Omron Sysmac Studio project EIP 自定义指令功能 20240814 (Sysmac Studio 1.50.0.64013, StandardProject)
(* 指令扩充 *)

# Controller new_Controller_0: NX102-1100 version 1.47
Task PrimaryTask (priority 4, period or condition 4000): program0

TYPE 机器人状态反馈1 : UNION
    motionstate1 : BYTE;
    state1 : ARRAY[0..7] OF BOOL;
END_UNION END_TYPE
TYPE 机器人状态反馈2 : UNION
    motionstate2 : BYTE;
    state2 : ARRAY[0..7] OF BOOL;
END_UNION END_TYPE
TYPE 机器人状态反馈3 : UNION
    motionstate3 : BYTE;
END_UNION END_TYPE
TYPE 机器人状态反馈4 : UNION
    motionstate4 : BYTE;
END_UNION END_TYPE

VAR_GLOBAL
    M0 : BOOL;  (* published *)
    M1 : BOOL;  (* published *)
    M2 : BOOL;  (* published *)
    M3 : BOOL;  (* published *)
    RobotCMD : UINT;
    RobotCMDLength : BYTE;
    RobotCMDState : BYTE;
    Robot_Header : ARRAY[0..5] OF BYTE;
    Robot_CMDHeader : ARRAY[0..9] OF BYTE;
    Robot_CMDPayload : ARRAY[0..119] OF BYTE;
    Robot_CyclicData : ARRAY[0..118] OF BYTE;
    Robot_Fooder : BYTE;
    M100 : BOOL;  (* published *)
    M101 : BOOL;  (* published *)
    M102 : BOOL;  (* published *)
    M103 : BOOL;  (* published *)
    M200 : BOOL;  (* published *)
    M201 : BOOL;  (* published *)
    M202 : BOOL;  (* published *)
    M203 : BOOL;  (* published *)
    M300 : BOOL;  (* published *)
    M301 : BOOL;  (* published *)
    M302 : BOOL;  (* network output *)
    M303 : BOOL;  (* network output *)
    M304 : BOOL;  (* network output *)
    M305 : BOOL;  (* network output *)
    M306 : BOOL;  (* network output *)
    EnableState : BOOL;
    R218L : BYTE;  (* network input *)
    R205 : REAL;  (* network input *)
    R207 : REAL;  (* network input *)
    R209 : REAL;  (* network input *)
    R211 : REAL;  (* network input *)
    R213 : REAL;  (* network input *)
    R215 : REAL;  (* network input *)
    R252 : UINT;  (* network output *)
    R218 : UINT;  (* network output *)
    R160 : REAL;  (* network output *)
    R105L : BYTE;  (* network input *)
    R162 : REAL;  (* network output *)
    R164 : REAL;  (* network output *)
    R166 : REAL;  (* network output *)
    R168 : REAL;  (* network output *)
    R170 : REAL;  (* network output *)
    R152 : UINT;  (* network output *)
    R352 : UINT;  (* network output *)
    R325L : BYTE;  (* network input *)
    R317 : REAL;  (* network input *)
    R319 : REAL;  (* network input *)
    R305 : REAL;  (* network input *)
    R307 : REAL;  (* network input *)
    R309 : REAL;  (* network input *)
    R311 : REAL;  (* network input *)
    R312 : REAL;  (* network input *)
    R313 : REAL;  (* network input *)
    R315 : REAL;  (* network input *)
    R12 : UINT;  (* published *)
    M400 : BOOL;  (* published *)
    R425L : BYTE;  (* published *)
    R417 : REAL;  (* published *)
    R419 : REAL;  (* published *)
    R405 : REAL;  (* published *)
    R407 : REAL;  (* published *)
    R409 : REAL;  (* published *)
    R411 : REAL;  (* published *)
    R413 : REAL;  (* published *)
    R415 : REAL;  (* published *)
    M401 : BOOL;  (* published *)
    M402 : BOOL;  (* published *)
    M404 : BOOL;  (* published *)
    M405 : BOOL;  (* published *)
    M406 : BOOL;  (* published *)
    M403 : BOOL;  (* published *)
    R452 : UINT;  (* published *)
    M500 : BOOL;  (* published *)
    R525L : BYTE;  (* published *)
    R525H : BYTE;  (* published *)
    R517 : REAL;  (* published *)
    R519 : REAL;  (* published *)
    R505 : REAL;  (* published *)
    R507 : REAL;  (* published *)
    R509 : REAL;  (* published *)
    R511 : REAL;  (* published *)
    R513 : REAL;  (* published *)
    R515 : REAL;  (* published *)
    M501 : BOOL;  (* published *)
    M502 : BOOL;  (* published *)
    M503 : BOOL;  (* published *)
    M504 : BOOL;  (* published *)
    M505 : BOOL;  (* published *)
    M506 : BOOL;  (* published *)
    R552 : UINT;  (* published *)
    B0 : BOOL;  (* LINK; published *)
    PLC_Header : ARRAY[0..5] OF BYTE;
    PLC_CMDHeader : ARRAY[0..9] OF BYTE;
    PLC_CMDPayload : ARRAY[0..238] OF BYTE;
    TOOLDATA_X : REAL;  (* published *)
    TOOLDATA_Y : REAL;  (* published *)
    TOOLDATA_Z : REAL;  (* published *)
    TOOLDATA_RX : REAL;  (* published *)
    TOOLDATA_RY : REAL;  (* published *)
    TOOLDATA_RZ : REAL;  (* published *)
    ROBOT_J1 : REAL;  (* published *)
    ROBOT_J2 : REAL;  (* published *)
    ROBOT_J3 : REAL;  (* published *)
    ROBOT_J4 : REAL;  (* published *)
    ROBOT_J5 : REAL;  (* published *)
    ROBOT_J6 : REAL;  (* published *)
    ROBOT_TOOLNO : BYTE;  (* published *)
    ROBOT_FRAMENO : BYTE;  (* published *)
    B1 : BOOL;  (* 已使能; published *)
    B2 : BOOL;  (* 运动完成; published *)
    B3 : BOOL;  (* 自动模式; published *)
    B4 : BOOL;  (* 手动模式; published *)
    B5 : BOOL;  (* 本地模式; published *)
    B6 : BOOL;  (* 远程模式; published *)
    B7 : BOOL;  (* 停止; published *)
    B8 : BOOL;  (* 运行; published *)
    B9 : BOOL;  (* 暂停; published *)
    B10 : BOOL;  (* 拖动; published *)
    B11 : BOOL;  (* 机器人报错; published *)
    Joint_Move : BOOL;  (* published *)
    Cartesian_Move : BOOL;  (* published *)
    EIP_OUT : ARRAY[0..255] OF BYTE;  (* network output *)
    EIP_IN : ARRAY[0..255] OF BYTE;  (* network input *)
    RobotCMDErrorcode : BYTE;  (* published *)
    R218H : BYTE;  (* published *)
    R217L : BYTE;  (* published *)
    R217H : BYTE;  (* published *)
    R172L : BYTE;  (* published *)
    R172H : BYTE;  (* published *)
    R173L : BYTE;  (* published *)
    M600 : BOOL;  (* published *)
    M601 : BOOL;  (* published *)
    M602 : BOOL;  (* published *)
    M604 : BOOL;  (* published *)
    M603 : BOOL;  (* published *)
    M700 : BOOL;  (* published *)
    M800 : BOOL;  (* published *)
    M900 : BOOL;  (* published *)
    M1000 : BOOL;  (* published *)
    M1100 : BOOL;  (* published *)
    M1200 : BOOL;  (* published *)
    M1300 : BOOL;  (* published *)
    M1400 : BOOL;  (* published *)
    M1500 : BOOL;  (* published *)
    M1600 : BOOL;  (* published *)
    M1700 : BOOL;  (* published *)
    M1800 : BOOL;  (* published *)
    M1900 : BOOL;  (* published *)
    M2000 : BOOL;  (* published *)
    M2100 : BOOL;  (* published *)
    M2200 : BOOL;  (* published *)
    M2300 : BOOL;  (* published *)
    M2401 : BOOL;  (* published *)
    M2402 : BOOL;  (* published *)
    M2403 : BOOL;  (* published *)
    M2404 : BOOL;  (* published *)
    M2405 : BOOL;  (* published *)
    M2406 : BOOL;  (* published *)
    M2407 : BOOL;  (* published *)
    M2408 : BOOL;  (* published *)
    M2400 : BOOL;  (* published *)
    R652 : UINT;  (* published *)
    M701 : BOOL;  (* published *)
    M702 : BOOL;  (* published *)
    M703 : BOOL;  (* published *)
    M704 : BOOL;  (* published *)
    M705 : BOOL;  (* published *)
    R752 : UINT;  (* published *)
    R805L : BYTE;  (* published *)
    R805H : BYTE;  (* published *)
    M801 : BOOL;  (* published *)
    M802 : BOOL;  (* published *)
    M804 : BOOL;  (* published *)
    M803 : BOOL;  (* published *)
    M805 : BOOL;  (* published *)
    M806 : BOOL;  (* published *)
    M807 : BOOL;  (* published *)
    M808 : BOOL;  (* published *)
    R852 : UINT;  (* published *)
    R905 : UINT;  (* published *)
    M901 : BOOL;  (* published *)
    M902 : BOOL;  (* published *)
    M904 : BOOL;  (* published *)
    M903 : BOOL;  (* published *)
    R952 : UINT;  (* published *)
    M1001 : BOOL;  (* published *)
    M1002 : BOOL;  (* published *)
    M1004 : BOOL;  (* published *)
    M1003 : BOOL;  (* published *)
    R1052 : UINT;  (* published *)
    M1101 : BOOL;  (* published *)
    M1102 : BOOL;  (* published *)
    M1104 : BOOL;  (* published *)
    M1105 : BOOL;  (* published *)
    M1103 : BOOL;  (* published *)
    R1152 : UINT;  (* published *)
    R1205 : REAL;  (* published *)
    R1207 : REAL;  (* published *)
    R1209 : REAL;  (* published *)
    R1211 : REAL;  (* published *)
    R1213 : REAL;  (* published *)
    R1215 : REAL;  (* published *)
    M1201 : BOOL;  (* published *)
    M1202 : BOOL;  (* published *)
    M1204 : BOOL;  (* published *)
    M1203 : BOOL;  (* published *)
    R1252 : UINT;  (* published *)
    R1305 : REAL;  (* published *)
    R1307 : REAL;  (* published *)
    R1309 : REAL;  (* published *)
    R1311 : REAL;  (* published *)
    R1313 : REAL;  (* published *)
    R1315 : REAL;  (* published *)
    R1317 : DINT;  (* published *)
    R1319L : BYTE;  (* published *)
    M1301 : BOOL;  (* published *)
    M1302 : BOOL;  (* published *)
    M1304 : BOOL;  (* published *)
    M1303 : BOOL;  (* published *)
    R1352 : UINT;  (* published *)
    R1417L : BYTE;  (* published *)
    R1405 : REAL;  (* published *)
    R1407 : REAL;  (* published *)
    R1409 : REAL;  (* published *)
    R1411 : REAL;  (* published *)
    R1413 : REAL;  (* published *)
    R1415 : REAL;  (* published *)
    R1417H : BYTE;  (* published *)
    M1401 : BOOL;  (* published *)
    M1402 : BOOL;  (* published *)
    M1403 : BOOL;  (* published *)
    M1404 : BOOL;  (* published *)
    M1405 : BOOL;  (* published *)
    M1406 : BOOL;  (* published *)
    R1452 : UINT;  (* published *)
    M1501 : BOOL;  (* published *)
    M1502 : BOOL;  (* published *)
    M1504 : BOOL;  (* published *)
    M1503 : BOOL;  (* published *)
    R1552 : UINT;  (* published *)
    R1565 : REAL;  (* published *)
    R1505L : BYTE;  (* published *)
    R1567L : BYTE;  (* published *)
    R1555 : REAL;  (* published *)
    R1557 : REAL;  (* published *)
    R1559 : REAL;  (* published *)
    R1561 : REAL;  (* published *)
    R1563 : REAL;  (* published *)
    M1601 : BOOL;  (* published *)
    M1602 : BOOL;  (* published *)
    M1604 : BOOL;  (* published *)
    M1605 : BOOL;  (* published *)
    M1606 : BOOL;  (* published *)
    M1603 : BOOL;  (* published *)
    R1613L : BYTE;  (* published *)
    R1652 : UINT;  (* published *)
    R1705L : BYTE;  (* published *)
    M1701 : BOOL;  (* published *)
    M1702 : BOOL;  (* published *)
    M1704 : BOOL;  (* published *)
    M1703 : BOOL;  (* published *)
    R1752 : UINT;  (* published *)
    R1763L : BYTE;  (* published *)
    R1755 : REAL;  (* published *)
    R1757 : REAL;  (* published *)
    R1759 : REAL;  (* published *)
    R1761 : REAL;  (* published *)
    M1801 : BOOL;  (* published *)
    M1802 : BOOL;  (* published *)
    M1804 : BOOL;  (* published *)
    M1803 : BOOL;  (* published *)
    R1852 : UINT;  (* published *)
    R1805 : REAL;  (* published *)
    R1807 : REAL;  (* published *)
    M1901 : BOOL;  (* published *)
    M1902 : BOOL;  (* published *)
    M1903 : BOOL;  (* published *)
    R1952 : UINT;  (* published *)
    R1955 : REAL;  (* published *)
    R1957 : REAL;  (* published *)
    R2005 : REAL;  (* published *)
    R2007 : REAL;  (* published *)
    M2001 : BOOL;  (* published *)
    M2002 : BOOL;  (* published *)
    M2004 : BOOL;  (* published *)
    M2003 : BOOL;  (* published *)
    R2052 : UINT;  (* published *)
    M2101 : BOOL;  (* published *)
    M2102 : BOOL;  (* published *)
    M2104 : BOOL;  (* published *)
    M2103 : BOOL;  (* published *)
    R2152 : UINT;  (* published *)
    R2155 : REAL;  (* published *)
    R2157 : REAL;  (* published *)
    R2205 : REAL;  (* published *)
    R2207 : REAL;  (* published *)
    R2209 : REAL;  (* published *)
    R2211 : REAL;  (* published *)
    R2213 : REAL;  (* published *)
    R2215 : REAL;  (* published *)
    R2217 : REAL;  (* published *)
    R2219 : REAL;  (* published *)
    R2221 : REAL;  (* published *)
    R2223 : REAL;  (* published *)
    R2225 : REAL;  (* published *)
    R2227 : REAL;  (* published *)
    M2201 : BOOL;  (* published *)
    M2202 : BOOL;  (* published *)
    M2204 : BOOL;  (* published *)
    M2203 : BOOL;  (* published *)
    R2257 : UINT;  (* published *)
    M2301 : BOOL;  (* published *)
    M2302 : BOOL;  (* published *)
    M2304 : BOOL;  (* published *)
    M2303 : BOOL;  (* published *)
    R2357 : REAL;  (* published *)
    R2355 : REAL;  (* published *)
    R2359 : REAL;  (* published *)
    R2361 : REAL;  (* published *)
    R2363 : REAL;  (* published *)
    R2365 : REAL;  (* published *)
    R2367 : REAL;  (* published *)
    R2369 : REAL;  (* published *)
    R2371 : REAL;  (* published *)
    R2373 : REAL;  (* published *)
    R2375 : REAL;  (* published *)
    R2377 : REAL;  (* published *)
    R2457 : UINT;  (* published *)
    R2405 : REAL;  (* published *)
    R2407 : REAL;  (* published *)
    R2409 : REAL;  (* published *)
    R2411L : BYTE;  (* published *)
    R2411H : BYTE;  (* published *)
    R2412L : BYTE;  (* published *)
    R1605 : REAL;  (* published *)
    R1607 : REAL;  (* published *)
    R1609 : REAL;  (* published *)
    R1611 : REAL;  (* published *)
    R855 : REAL;  (* published *)
    R857 : REAL;  (* published *)
    R859 : REAL;  (* published *)
    R861 : REAL;  (* published *)
    R863 : REAL;  (* published *)
    R865 : REAL;  (* published *)
    R867 : REAL;  (* published *)
    R869 : REAL;  (* published *)
    R871 : REAL;  (* published *)
    R873 : REAL;  (* published *)
    R875 : REAL;  (* published *)
    R877 : REAL;  (* published *)
    R879L : BYTE;  (* published *)
    R879H : BYTE;  (* published *)
    R880L : BYTE;  (* published *)
    R880H : BYTE;  (* published *)
    R881L : BYTE;  (* published *)
    R881H : BYTE;  (* published *)
    R882L : BYTE;  (* published *)
    JointIN : ARRAY[0..5] OF REAL;  (* published *)
    CartestionReturn : ARRAY[0..5] OF REAL;  (* published *)
    CartestionIN : ARRAY[0..5] OF REAL;  (* published *)
    JointReturn : ARRAY[0..5] OF REAL;  (* published *)
END_VAR

PROGRAM program0
VAR
    WriteTool : RC_WriteToolData;
    MCPower : RC_EnableRobot;
    ReadTool : RC_ReadToolData;
    MoveA : RC_MoveAxesAbsolute;
    ReadActPosition : RC_ReadActualPosition;
    W1 : INT;
    Lifesign : ARRAY[0..1] OF BYTE;
    TooNoIN : BYTE;
    ToolData_IN : ARRAY[0..5] OF REAL;
    TooNo_IN : BYTE;
    MoveLine : RC_MoveLinearAbsolute;
    MoveDirect : RC_MoveDirectAbsolute;
    ROBOT_STATE1 : 机器人状态反馈1;
    ROBOT_STATE2 : 机器人状态反馈2;
    ROBOT_STATE3 : 机器人状态反馈3;
    ROBOT_STATE4 : 机器人状态反馈4;
    STEP1 : UINT;
    START : BOOL;
    关节初始位置 : ARRAY[0..5] OF REAL;
    笛卡尔初始位置 : ARRAY[0..5] OF REAL;
    JOint_in : ARRAY[0..5] OF REAL;
    Cartesian_in : ARRAY[0..5] OF REAL;
    调试 : BOOL;
    调试1 : BOOL;
    调试2 : BOOL;
    调试3 : BOOL;
    自动运行 : BOOL;
    STEP2 : UINT;
    START1 : BOOL;
    ROBOT_MotionCount : UDINT;
    Count_Buffer : UDINT;
    count_Done : BOOL;
    GroupReset : RC_GroupReset;
    GroupStop : RC_GroupStop;
    ChangeSpeedOverride : RC_ChangeSpeedOverride;
    GroupContinue : RC_GroupContinue;
    GroupInterrupt : RC_GroupInterrupt;
    WriteFrameData : RC_WriteFrameData;
    ReadFrameData : RC_ReadFrameData;
    WriteLoadData : RC_WriteLoadData;
    ReadLoadData : RC_ReadLoadData;
    WriteRobotRerenceDynamics : RC_WriteRobotReferenceDynamics;
    ReadRobotRerfrenceDynamics : RC_ReadRobotReferenceDynamics;
    WriteRobotLimits : RC_WriteRobotSwLimits;
    ReadRobotLimits : RC_ReadRobotSwLimits;
    WriteRobotDefaultDynamic : RC_WriteRobotDefaultDynamic;
    ReadRobotDefaultDynamic : RC_ReadRobotDefaultDynamic;
    CartesionFromJoint : RC_CartesionFromJoint;
    JointFromCartesion : RC_JointFromCartesion;
    GroupJog : RC_GroupJog;
    ABC : _sTimer;
    DFG : _sTimer;
    EDF : _sTimer;
    done : BOOL;
    done1 : BOOL;
    done2 : BOOL;
    test1 : BOOL;
    test2 : BOOL;
    test3 : BOOL;
    test4 : BOOL;
    JKL : _sTimer;
    done3 : BOOL;
    ACB : _sTimer;
    DGF : _sTimer;
    EFD : _sTimer;
    JLK : _sTimer;
    ZXC : _sTimer;
    done4 : BOOL;
    ZCX : _sTimer;
    done5 : BOOL;
    CXZ : _sTimer;
    done6 : BOOL;
    done7 : BOOL;
    XCZ : _sTimer;
    done8 : BOOL;
    CZX : _sTimer;
    done9 : BOOL;
    XCV : _sTimer;
    done10 : BOOL;
END_VAR
VAR_EXTERNAL
    M0 : BOOL;
    M1 : BOOL;
    M2 : BOOL;
    M3 : BOOL;
    M100 : BOOL;
    M101 : BOOL;
    M201 : BOOL;
    M202 : BOOL;
    M203 : BOOL;
    R218L : BYTE;
    R205 : REAL;
    R207 : REAL;
    R209 : REAL;
    R211 : REAL;
    R213 : REAL;
    R215 : REAL;
    R252 : UINT;
    R218 : UINT;
    M102 : BOOL;
    M103 : BOOL;
    R160 : REAL;
    R162 : REAL;
    R164 : REAL;
    R166 : REAL;
    R168 : REAL;
    R170 : REAL;
    R152 : UINT;
    M200 : BOOL;
    R105L : BYTE;
    M300 : BOOL;
    M301 : BOOL;
    M302 : BOOL;
    M303 : BOOL;
    M304 : BOOL;
    M305 : BOOL;
    M306 : BOOL;
    R352 : UINT;
    R317 : REAL;
    R319 : REAL;
    R305 : REAL;
    R307 : REAL;
    R309 : REAL;
    R311 : REAL;
    R312 : REAL;
    R313 : REAL;
    R315 : REAL;
    R325L : BYTE;
    R12 : UINT;
    R425L : BYTE;
    R417 : REAL;
    R419 : REAL;
    R405 : REAL;
    R407 : REAL;
    R409 : REAL;
    R411 : REAL;
    R413 : REAL;
    R415 : REAL;
    M401 : BOOL;
    M402 : BOOL;
    M404 : BOOL;
    M405 : BOOL;
    M406 : BOOL;
    M403 : BOOL;
    R452 : UINT;
    M500 : BOOL;
    M400 : BOOL;
    R525L : BYTE;
    R525H : BYTE;
    R517 : REAL;
    R519 : REAL;
    R505 : REAL;
    R507 : REAL;
    R509 : REAL;
    R511 : REAL;
    R513 : REAL;
    R515 : REAL;
    M501 : BOOL;
    M502 : BOOL;
    M503 : BOOL;
    M504 : BOOL;
    M505 : BOOL;
    M506 : BOOL;
    R552 : UINT;
    Robot_Header : ARRAY[0..5] OF BYTE;
    B0 : BOOL;
    Robot_CMDHeader : ARRAY[0..9] OF BYTE;
    Robot_CMDPayload : ARRAY[0..119] OF BYTE;
    Robot_CyclicData : ARRAY[0..118] OF BYTE;
    ROBOT_J1 : REAL;
    ROBOT_J2 : REAL;
    ROBOT_J3 : REAL;
    ROBOT_J4 : REAL;
    ROBOT_J5 : REAL;
    ROBOT_J6 : REAL;
    TOOLDATA_X : REAL;
    TOOLDATA_Y : REAL;
    TOOLDATA_Z : REAL;
    TOOLDATA_RZ : REAL;
    TOOLDATA_RY : REAL;
    TOOLDATA_RX : REAL;
    ROBOT_TOOLNO : BYTE;
    ROBOT_FRAMENO : BYTE;
    B1 : BOOL;
    B3 : BOOL;
    B4 : BOOL;
    B5 : BOOL;
    B6 : BOOL;
    B2 : BOOL;
    B7 : BOOL;
    B8 : BOOL;
    B9 : BOOL;
    B10 : BOOL;
    B11 : BOOL;
    Joint_Move : BOOL;
    Cartesian_Move : BOOL;
    EIP_OUT : ARRAY[0..255] OF BYTE;
    EIP_IN : ARRAY[0..255] OF BYTE;
    RobotCMD : UINT;
    RobotCMDLength : BYTE;
    RobotCMDState : BYTE;
    RobotCMDErrorcode : BYTE;
    R217L : BYTE;
    R217H : BYTE;
    R172L : BYTE;
    R172H : BYTE;
    R173L : BYTE;
    M600 : BOOL;
    M601 : BOOL;
    M602 : BOOL;
    M604 : BOOL;
    M603 : BOOL;
    M700 : BOOL;
    M800 : BOOL;
    M900 : BOOL;
    M1000 : BOOL;
    M1100 : BOOL;
    M1200 : BOOL;
    M1300 : BOOL;
    M1400 : BOOL;
    M1500 : BOOL;
    M1600 : BOOL;
    M1700 : BOOL;
    M1800 : BOOL;
    M1900 : BOOL;
    M2000 : BOOL;
    M2100 : BOOL;
    M2200 : BOOL;
    M2300 : BOOL;
    M2401 : BOOL;
    M2402 : BOOL;
    M2403 : BOOL;
    M2404 : BOOL;
    M2405 : BOOL;
    M2406 : BOOL;
    M2407 : BOOL;
    M2408 : BOOL;
    M2400 : BOOL;
    R652 : UINT;
    M701 : BOOL;
    M702 : BOOL;
    M703 : BOOL;
    M704 : BOOL;
    M705 : BOOL;
    R752 : UINT;
    R805L : BYTE;
    R805H : BYTE;
    M801 : BOOL;
    M802 : BOOL;
    M804 : BOOL;
    M803 : BOOL;
    M805 : BOOL;
    M806 : BOOL;
    M807 : BOOL;
    M808 : BOOL;
    R852 : UINT;
    R905 : UINT;
    M901 : BOOL;
    M902 : BOOL;
    M904 : BOOL;
    M903 : BOOL;
    R952 : UINT;
    M1001 : BOOL;
    M1002 : BOOL;
    M1004 : BOOL;
    M1003 : BOOL;
    R1052 : UINT;
    M1101 : BOOL;
    M1102 : BOOL;
    M1104 : BOOL;
    M1105 : BOOL;
    M1103 : BOOL;
    R1152 : UINT;
    R1205 : REAL;
    R1207 : REAL;
    R1209 : REAL;
    R1211 : REAL;
    R1213 : REAL;
    R1215 : REAL;
    M1201 : BOOL;
    M1202 : BOOL;
    M1204 : BOOL;
    M1203 : BOOL;
    R1252 : UINT;
    R1305 : REAL;
    R1307 : REAL;
    R1309 : REAL;
    R1311 : REAL;
    R1313 : REAL;
    R1315 : REAL;
    R1317 : DINT;
    R1319L : BYTE;
    M1301 : BOOL;
    M1302 : BOOL;
    M1304 : BOOL;
    M1303 : BOOL;
    R1352 : UINT;
    R1417L : BYTE;
    R1405 : REAL;
    R1407 : REAL;
    R1409 : REAL;
    R1411 : REAL;
    R1413 : REAL;
    R1415 : REAL;
    R1417H : BYTE;
    M1401 : BOOL;
    M1402 : BOOL;
    M1403 : BOOL;
    M1404 : BOOL;
    M1405 : BOOL;
    M1406 : BOOL;
    R1452 : UINT;
    M1501 : BOOL;
    M1502 : BOOL;
    M1504 : BOOL;
    M1503 : BOOL;
    R1552 : UINT;
    R1505L : BYTE;
    R1567L : BYTE;
    R1555 : REAL;
    R1557 : REAL;
    R1559 : REAL;
    R1561 : REAL;
    R1563 : REAL;
    R1565 : REAL;
    M1601 : BOOL;
    M1602 : BOOL;
    M1604 : BOOL;
    M1605 : BOOL;
    M1606 : BOOL;
    M1603 : BOOL;
    R1613L : BYTE;
    R1652 : UINT;
    R1705L : BYTE;
    M1701 : BOOL;
    M1702 : BOOL;
    M1704 : BOOL;
    M1703 : BOOL;
    R1752 : UINT;
    R1763L : BYTE;
    R1755 : REAL;
    R1757 : REAL;
    R1759 : REAL;
    R1761 : REAL;
    M1801 : BOOL;
    M1802 : BOOL;
    M1804 : BOOL;
    M1803 : BOOL;
    R1852 : UINT;
    R1805 : REAL;
    R1807 : REAL;
    M1901 : BOOL;
    M1902 : BOOL;
    M1903 : BOOL;
    R1952 : UINT;
    R1955 : REAL;
    R1957 : REAL;
    R2005 : REAL;
    R2007 : REAL;
    M2001 : BOOL;
    M2002 : BOOL;
    M2004 : BOOL;
    M2003 : BOOL;
    R2052 : UINT;
    M2101 : BOOL;
    M2102 : BOOL;
    M2104 : BOOL;
    M2103 : BOOL;
    R2152 : UINT;
    R2155 : REAL;
    R2157 : REAL;
    R2205 : REAL;
    R2207 : REAL;
    R2209 : REAL;
    R2211 : REAL;
    R2213 : REAL;
    R2215 : REAL;
    R2217 : REAL;
    R2219 : REAL;
    R2221 : REAL;
    R2223 : REAL;
    R2225 : REAL;
    R2227 : REAL;
    M2201 : BOOL;
    M2202 : BOOL;
    M2204 : BOOL;
    M2203 : BOOL;
    R2257 : UINT;
    M2301 : BOOL;
    M2302 : BOOL;
    M2304 : BOOL;
    M2303 : BOOL;
    R2357 : REAL;
    R2355 : REAL;
    R2359 : REAL;
    R2361 : REAL;
    R2363 : REAL;
    R2365 : REAL;
    R2367 : REAL;
    R2369 : REAL;
    R2371 : REAL;
    R2373 : REAL;
    R2375 : REAL;
    R2377 : REAL;
    R2457 : UINT;
    R2405 : REAL;
    R2407 : REAL;
    R2409 : REAL;
    R2411L : BYTE;
    R2411H : BYTE;
    R2412L : BYTE;
    R1605 : REAL;
    R1607 : REAL;
    R1609 : REAL;
    R1611 : REAL;
    JointIN : ARRAY[0..5] OF REAL;
    CartestionIN : ARRAY[0..5] OF REAL;
END_VAR
VAR
    _e1 : R_TRIG;
    _e2 : F_TRIG;
    _e3 : R_TRIG;
    _e4 : R_TRIG;
    _e5 : R_TRIG;
    _e6 : R_TRIG;
    _e7 : R_TRIG;
    _e8 : R_TRIG;
    _e9 : R_TRIG;
    _e10 : R_TRIG;
    _e11 : R_TRIG;
    _e12 : R_TRIG;
    _e13 : R_TRIG;
    _e14 : R_TRIG;
    _e15 : R_TRIG;
    _e16 : R_TRIG;
    _e17 : R_TRIG;
    _e18 : R_TRIG;
    _e19 : R_TRIG;
    _e20 : R_TRIG;
    _e21 : R_TRIG;
    _e22 : R_TRIG;
    _e23 : R_TRIG;
    _e24 : R_TRIG;
    _e25 : R_TRIG;
    _e26 : R_TRIG;
    _e27 : F_TRIG;
    _t28 : BOOL;
    _p29 : BOOL;
    _t30 : BOOL;
    _p31 : BOOL;
    _t32 : BOOL;
    _p33 : BOOL;
    _t34 : BOOL;
    _p35 : BOOL;
    _t36 : BOOL;
    _p37 : BOOL;
    _t38 : BOOL;
    _p39 : BOOL;
    _t40 : BOOL;
    _p41 : BOOL;
    _t42 : BOOL;
    _p43 : BOOL;
    _t44 : BOOL;
    _p45 : BOOL;
    _t46 : BOOL;
    _p47 : BOOL;
    _t48 : BOOL;
    _p49 : BOOL;
    _t50 : BOOL;
    _p51 : BOOL;
    _t52 : BOOL;
    _p53 : BOOL;
    _t54 : BOOL;
    _p55 : BOOL;
END_VAR

(* Section Main: ladder, written here as Structured Text *)

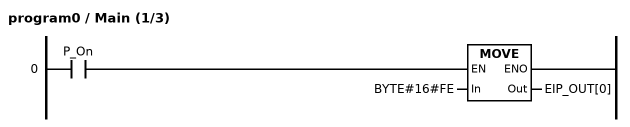
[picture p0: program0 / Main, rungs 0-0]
(* Rung 0 *)
IF P_On THEN EIP_OUT[0] := BYTE#16#FE; END_IF;

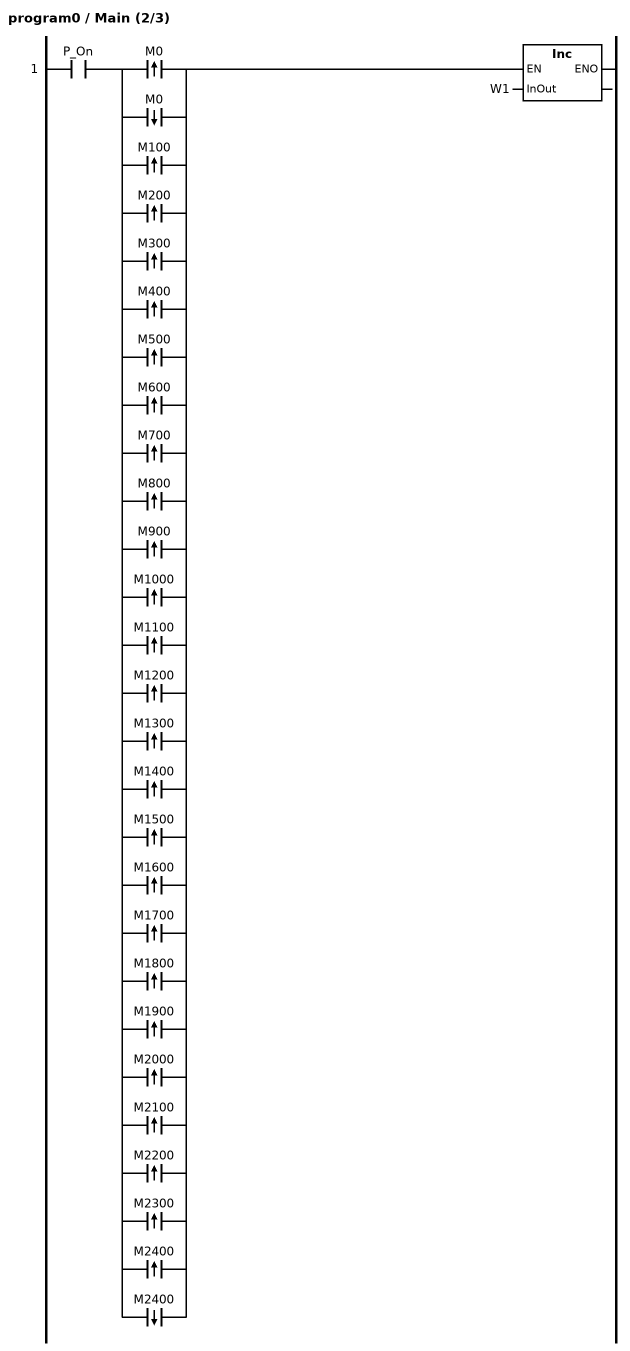
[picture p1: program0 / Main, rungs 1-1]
(* Rung 1 *)
_e1(CLK := M0);
_e2(CLK := M0);
_e3(CLK := M100);
_e4(CLK := M200);
_e5(CLK := M300);
_e6(CLK := M400);
_e7(CLK := M500);
_e8(CLK := M600);
_e9(CLK := M700);
_e10(CLK := M800);
_e11(CLK := M900);
_e12(CLK := M1000);
_e13(CLK := M1100);
_e14(CLK := M1200);
_e15(CLK := M1300);
_e16(CLK := M1400);
_e17(CLK := M1500);
_e18(CLK := M1600);
_e19(CLK := M1700);
_e20(CLK := M1800);
_e21(CLK := M1900);
_e22(CLK := M2000);
_e23(CLK := M2100);
_e24(CLK := M2200);
_e25(CLK := M2300);
_e26(CLK := M2400);
_e27(CLK := M2400);
IF P_On AND (_e1.Q OR _e2.Q OR _e3.Q OR _e4.Q OR _e5.Q OR _e6.Q OR _e7.Q OR _e8.Q OR _e9.Q OR _e10.Q OR _e11.Q OR _e12.Q OR _e13.Q OR _e14.Q OR _e15.Q OR _e16.Q OR _e17.Q OR _e18.Q OR _e19.Q OR _e20.Q OR _e21.Q OR _e22.Q OR _e23.Q OR _e24.Q OR _e25.Q OR _e26.Q OR _e27.Q) THEN
    Inc(InOut := W1);
END_IF;

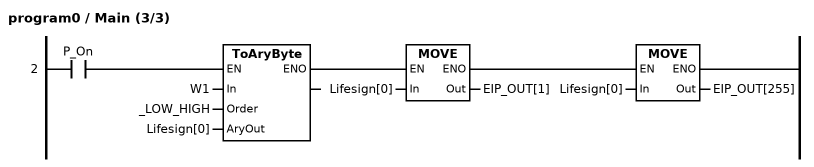
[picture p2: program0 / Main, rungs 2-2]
(* Rung 2 *)
IF P_On THEN
    ToAryByte(In := W1, Order := _LOW_HIGH, AryOut := Lifesign[0]);
    EIP_OUT[1] := Lifesign[0];
    EIP_OUT[255] := Lifesign[0];
END_IF;

(* Section Main1: ladder, written here as Structured Text *)

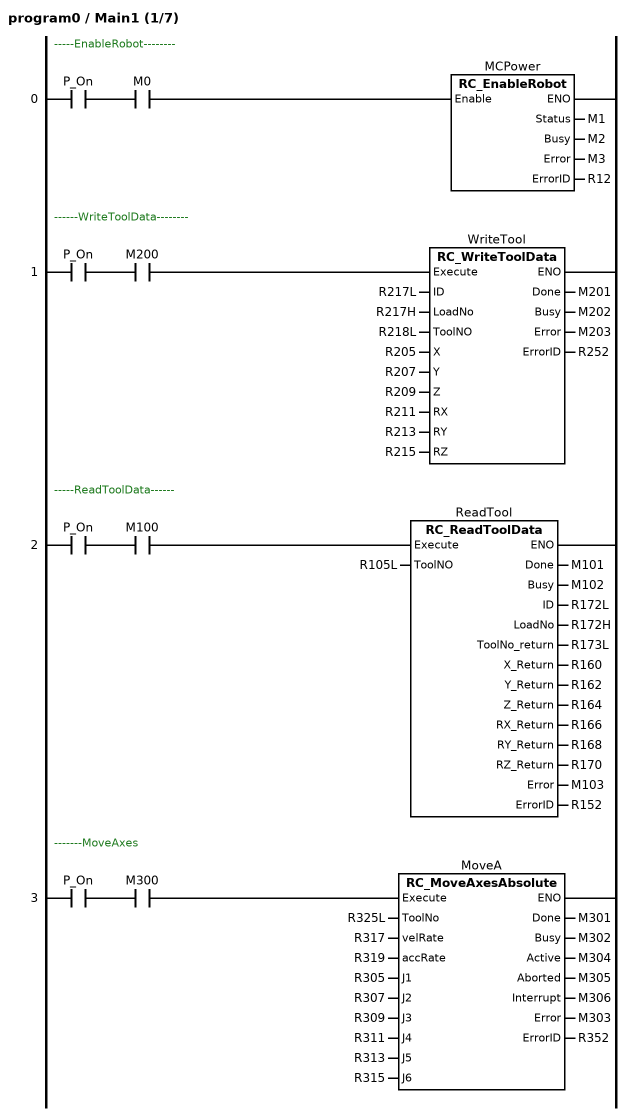
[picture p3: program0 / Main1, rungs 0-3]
(* Rung 0: -----EnableRobot-------- *)
MCPower(Enable := P_On AND M0, Status => M1, Busy => M2, Error => M3, ErrorID => R12);
(* Rung 1: ------WriteToolData-------- *)
WriteTool(Execute := P_On AND M200, ID := R217L, LoadNo := R217H, ToolNO := R218L, X := R205, Y := R207, Z := R209, RX := R211, RY := R213, RZ := R215, Done => M201, Busy => M202, Error => M203, ErrorID => R252);
(* Rung 2: -----ReadToolData------ *)
ReadTool(Execute := P_On AND M100, ToolNO := R105L, Done => M101, Busy => M102, ID => R172L, LoadNo => R172H, ToolNo_return => R173L, X_Return => R160, Y_Return => R162, Z_Return => R164, RX_Return => R166, RY_Return => R168, RZ_Return => R170, Error => M103, ErrorID => R152);
(* Rung 3: -------MoveAxes *)
MoveA(Execute := P_On AND M300, ToolNo := R325L, velRate := R317, accRate := R319, J1 := R305, J2 := R307, J3 := R309, J4 := R311, J5 := R313, J6 := R315, Done => M301, Busy => M302, Active => M304, Aborted => M305, Interrupt => M306, Error => M303, ErrorID => R352);

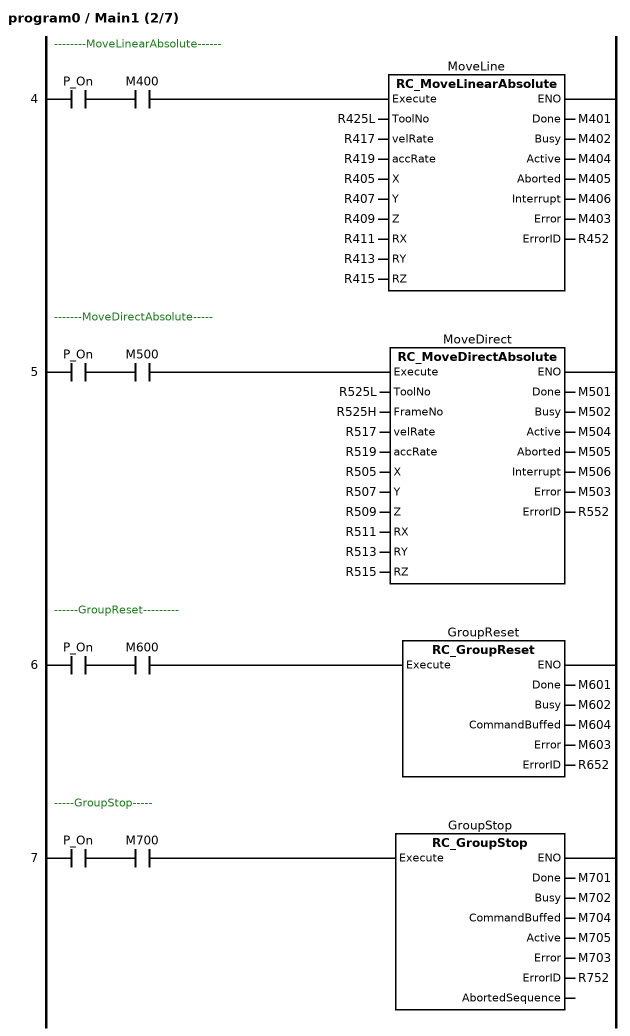
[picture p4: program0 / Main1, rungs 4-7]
(* Rung 4: --------MoveLinearAbsolute------ *)
MoveLine(Execute := P_On AND M400, ToolNo := R425L, velRate := R417, accRate := R419, X := R405, Y := R407, Z := R409, RX := R411, RY := R413, RZ := R415, Done => M401, Busy => M402, Active => M404, Aborted => M405, Interrupt => M406, Error => M403, ErrorID => R452);
(* Rung 5: -------MoveDirectAbsolute----- *)
MoveDirect(Execute := P_On AND M500, ToolNo := R525L, FrameNo := R525H, velRate := R517, accRate := R519, X := R505, Y := R507, Z := R509, RX := R511, RY := R513, RZ := R515, Done => M501, Busy => M502, Active => M504, Aborted => M505, Interrupt => M506, Error => M503, ErrorID => R552);
(* Rung 6: ------GroupReset--------- *)
GroupReset(Execute := P_On AND M600, Done => M601, Busy => M602, CommandBuffed => M604, Error => M603, ErrorID => R652);
(* Rung 7: -----GroupStop----- *)
GroupStop(Execute := P_On AND M700, Done => M701, Busy => M702, CommandBuffed => M704, Active => M705, Error => M703, ErrorID => R752);

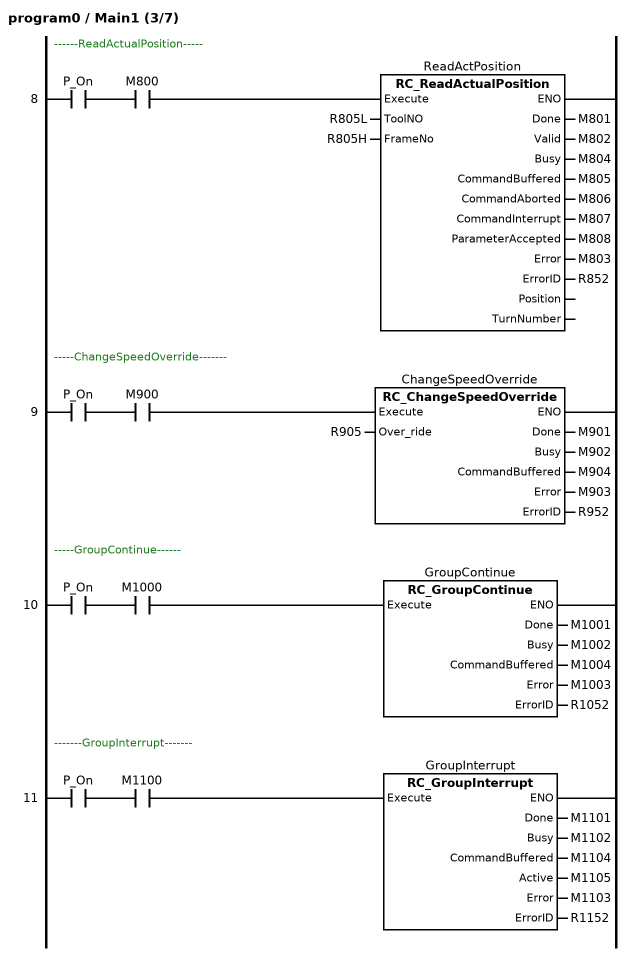
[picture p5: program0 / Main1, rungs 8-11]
(* Rung 8: ------ReadActualPosition----- *)
ReadActPosition(Execute := P_On AND M800, ToolNO := R805L, FrameNo := R805H, Done => M801, Valid => M802, Busy => M804, CommandBuffered => M805, CommandAborted => M806, CommandInterrupt => M807, ParameterAccepted => M808, Error => M803, ErrorID => R852);
(* Rung 9: -----ChangeSpeedOverride------- *)
ChangeSpeedOverride(Execute := P_On AND M900, Over_ride := R905, Done => M901, Busy => M902, CommandBuffered => M904, Error => M903, ErrorID => R952);
(* Rung 10: -----GroupContinue------ *)
GroupContinue(Execute := P_On AND M1000, Done => M1001, Busy => M1002, CommandBuffered => M1004, Error => M1003, ErrorID => R1052);
(* Rung 11: -------GroupInterrupt------- *)
GroupInterrupt(Execute := P_On AND M1100, Done => M1101, Busy => M1102, CommandBuffered => M1104, Active => M1105, Error => M1103, ErrorID => R1152);

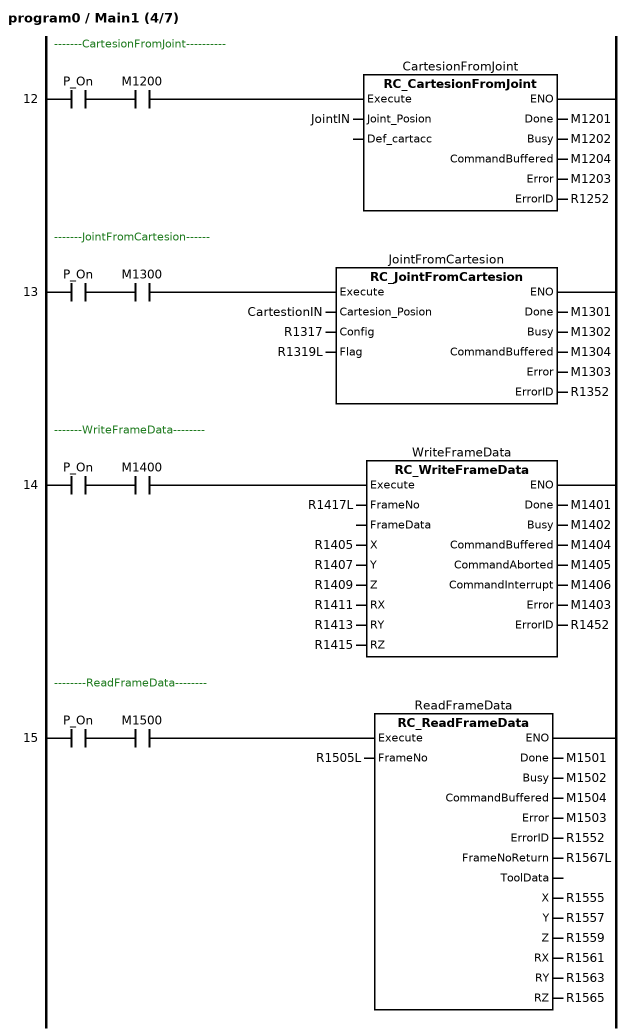
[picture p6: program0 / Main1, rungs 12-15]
(* Rung 12: -------CartesionFromJoint---------- *)
CartesionFromJoint(Execute := P_On AND M1200, Joint_Posion := JointIN, Done => M1201, Busy => M1202, CommandBuffered => M1204, Error => M1203, ErrorID => R1252);
(* Rung 13: -------JointFromCartesion------ *)
JointFromCartesion(Execute := P_On AND M1300, Cartesion_Posion := CartestionIN, Config := R1317, Flag := R1319L, Done => M1301, Busy => M1302, CommandBuffered => M1304, Error => M1303, ErrorID => R1352);
(* Rung 14: -------WriteFrameData-------- *)
WriteFrameData(Execute := P_On AND M1400, FrameNo := R1417L, X := R1405, Y := R1407, Z := R1409, RX := R1411, RY := R1413, RZ := R1415, Done => M1401, Busy => M1402, CommandBuffered => M1404, CommandAborted => M1405, CommandInterrupt => M1406, Error => M1403, ErrorID => R1452);
(* Rung 15: --------ReadFrameData-------- *)
ReadFrameData(Execute := P_On AND M1500, FrameNo := R1505L, Done => M1501, Busy => M1502, CommandBuffered => M1504, Error => M1503, ErrorID => R1552, FrameNoReturn => R1567L, X => R1555, Y => R1557, Z => R1559, RX => R1561, RY => R1563, RZ => R1565);

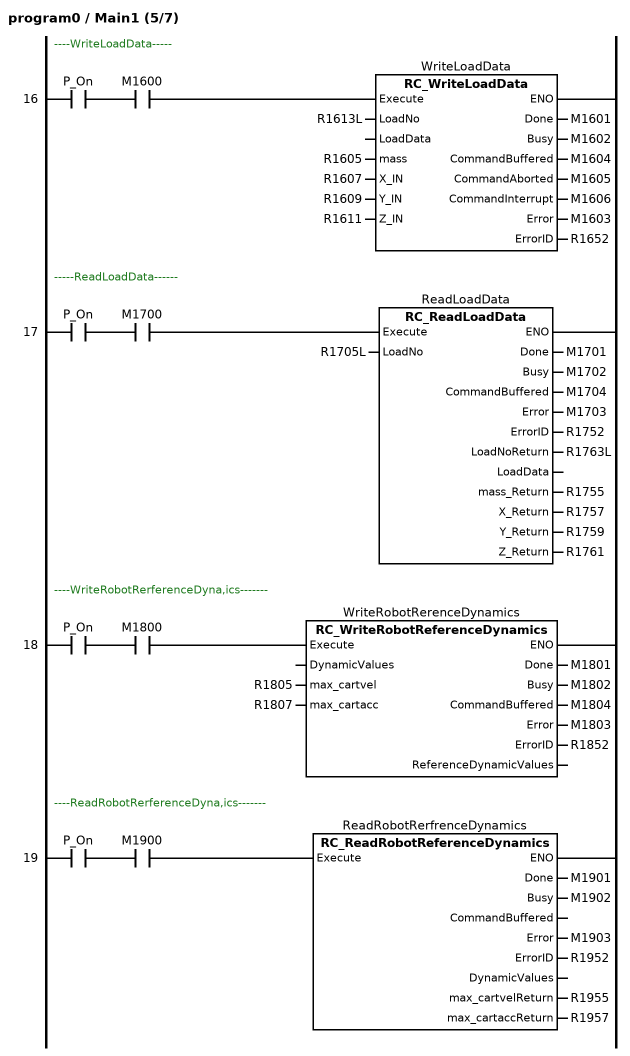
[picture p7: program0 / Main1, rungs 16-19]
(* Rung 16: ----WriteLoadData----- *)
WriteLoadData(Execute := P_On AND M1600, LoadNo := R1613L, mass := R1605, X_IN := R1607, Y_IN := R1609, Z_IN := R1611, Done => M1601, Busy => M1602, CommandBuffered => M1604, CommandAborted => M1605, CommandInterrupt => M1606, Error => M1603, ErrorID => R1652);
(* Rung 17: -----ReadLoadData------ *)
ReadLoadData(Execute := P_On AND M1700, LoadNo := R1705L, Done => M1701, Busy => M1702, CommandBuffered => M1704, Error => M1703, ErrorID => R1752, LoadNoReturn => R1763L, mass_Return => R1755, X_Return => R1757, Y_Return => R1759, Z_Return => R1761);
(* Rung 18: ----WriteRobotRerferenceDyna,ics------- *)
WriteRobotRerenceDynamics(Execute := P_On AND M1800, max_cartvel := R1805, max_cartacc := R1807, Done => M1801, Busy => M1802, CommandBuffered => M1804, Error => M1803, ErrorID => R1852);
(* Rung 19: ----ReadRobotRerferenceDyna,ics------- *)
ReadRobotRerfrenceDynamics(Execute := P_On AND M1900, Done => M1901, Busy => M1902, Error => M1903, ErrorID => R1952, max_cartvelReturn => R1955, max_cartaccReturn => R1957);

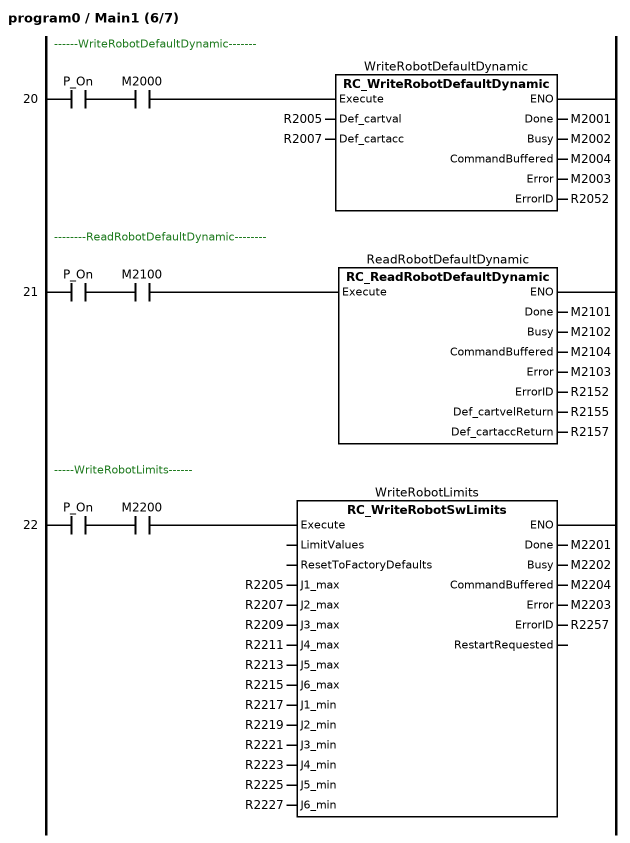
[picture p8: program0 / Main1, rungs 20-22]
(* Rung 20: ------WriteRobotDefaultDynamic------- *)
WriteRobotDefaultDynamic(Execute := P_On AND M2000, Def_cartval := R2005, Def_cartacc := R2007, Done => M2001, Busy => M2002, CommandBuffered => M2004, Error => M2003, ErrorID => R2052);
(* Rung 21: --------ReadRobotDefaultDynamic-------- *)
ReadRobotDefaultDynamic(Execute := P_On AND M2100, Done => M2101, Busy => M2102, CommandBuffered => M2104, Error => M2103, ErrorID => R2152, Def_cartvelReturn => R2155, Def_cartaccReturn => R2157);
(* Rung 22: -----WriteRobotLimits------ *)
WriteRobotLimits(Execute := P_On AND M2200, J1_max := R2205, J2_max := R2207, J3_max := R2209, J4_max := R2211, J5_max := R2213, J6_max := R2215, J1_min := R2217, J2_min := R2219, J3_min := R2221, J4_min := R2223, J5_min := R2225, J6_min := R2227, Done => M2201, Busy => M2202, CommandBuffered => M2204, Error => M2203, ErrorID => R2257);

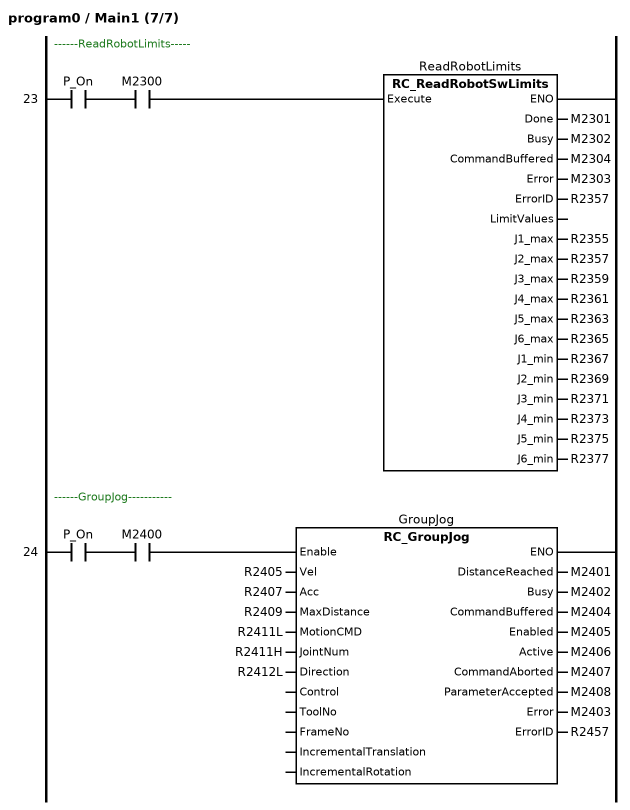
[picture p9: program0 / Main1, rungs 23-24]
(* Rung 23: ------ReadRobotLimits----- *)
ReadRobotLimits(Execute := P_On AND M2300, Done => M2301, Busy => M2302, CommandBuffered => M2304, Error => M2303, ErrorID => R2357, J1_max => R2355, J2_max => R2357, J3_max => R2359, J4_max => R2361, J5_max => R2363, J6_max => R2365, J1_min => R2367, J2_min => R2369, J3_min => R2371, J4_min => R2373, J5_min => R2375, J6_min => R2377);
(* Rung 24: ------GroupJog----------- *)
GroupJog(Enable := P_On AND M2400, Vel := R2405, Acc := R2407, MaxDistance := R2409, MotionCMD := R2411L, JointNum := R2411H, Direction := R2412L, DistanceReached => M2401, Busy => M2402, CommandBuffered => M2404, Enabled => M2405, Active => M2406, CommandAborted => M2407, ParameterAccepted => M2408, Error => M2403, ErrorID => R2457);

(* Section cyclicdata: ladder, written here as Structured Text *)

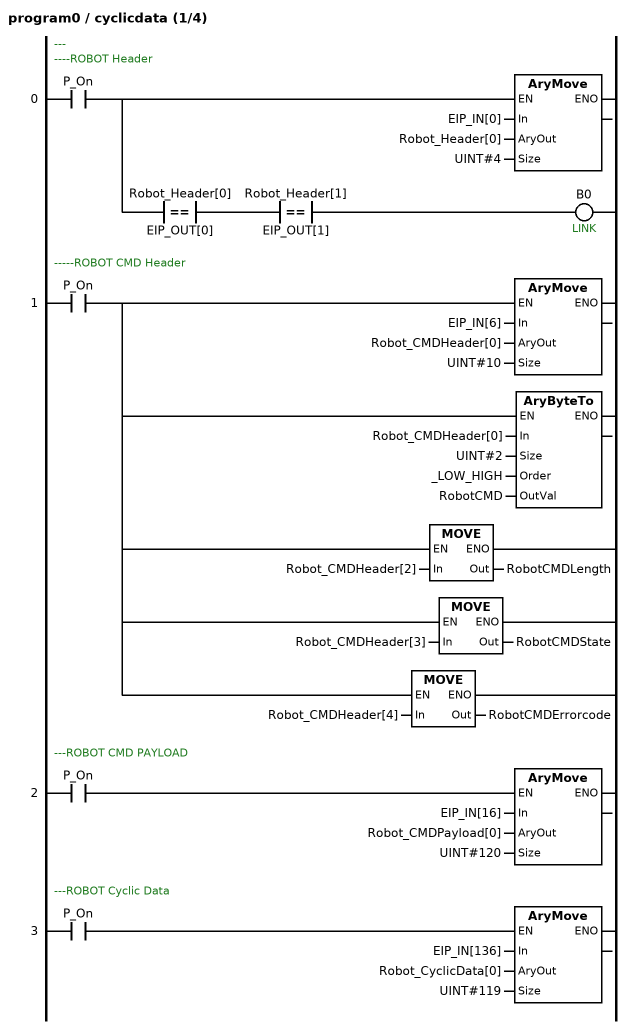
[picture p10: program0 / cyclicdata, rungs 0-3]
(* Rung 0: --- / ----ROBOT Header *)
IF P_On THEN AryMove(In := EIP_IN[0], AryOut := Robot_Header[0], Size := UINT#4); END_IF;
B0 := P_On AND (Robot_Header[0] = EIP_OUT[0]) AND (Robot_Header[1] = EIP_OUT[1]);
(* Rung 1: -----ROBOT CMD Header *)
IF P_On THEN
    AryMove(In := EIP_IN[6], AryOut := Robot_CMDHeader[0], Size := UINT#10);
    AryByteTo(In := Robot_CMDHeader[0], Size := UINT#2, Order := _LOW_HIGH, OutVal := RobotCMD);
    RobotCMDLength := Robot_CMDHeader[2];
    RobotCMDState := Robot_CMDHeader[3];
    RobotCMDErrorcode := Robot_CMDHeader[4];
END_IF;
(* Rung 2: ---ROBOT CMD PAYLOAD *)
IF P_On THEN AryMove(In := EIP_IN[16], AryOut := Robot_CMDPayload[0], Size := UINT#120); END_IF;
(* Rung 3: ---ROBOT Cyclic Data *)
IF P_On THEN AryMove(In := EIP_IN[136], AryOut := Robot_CyclicData[0], Size := UINT#119); END_IF;

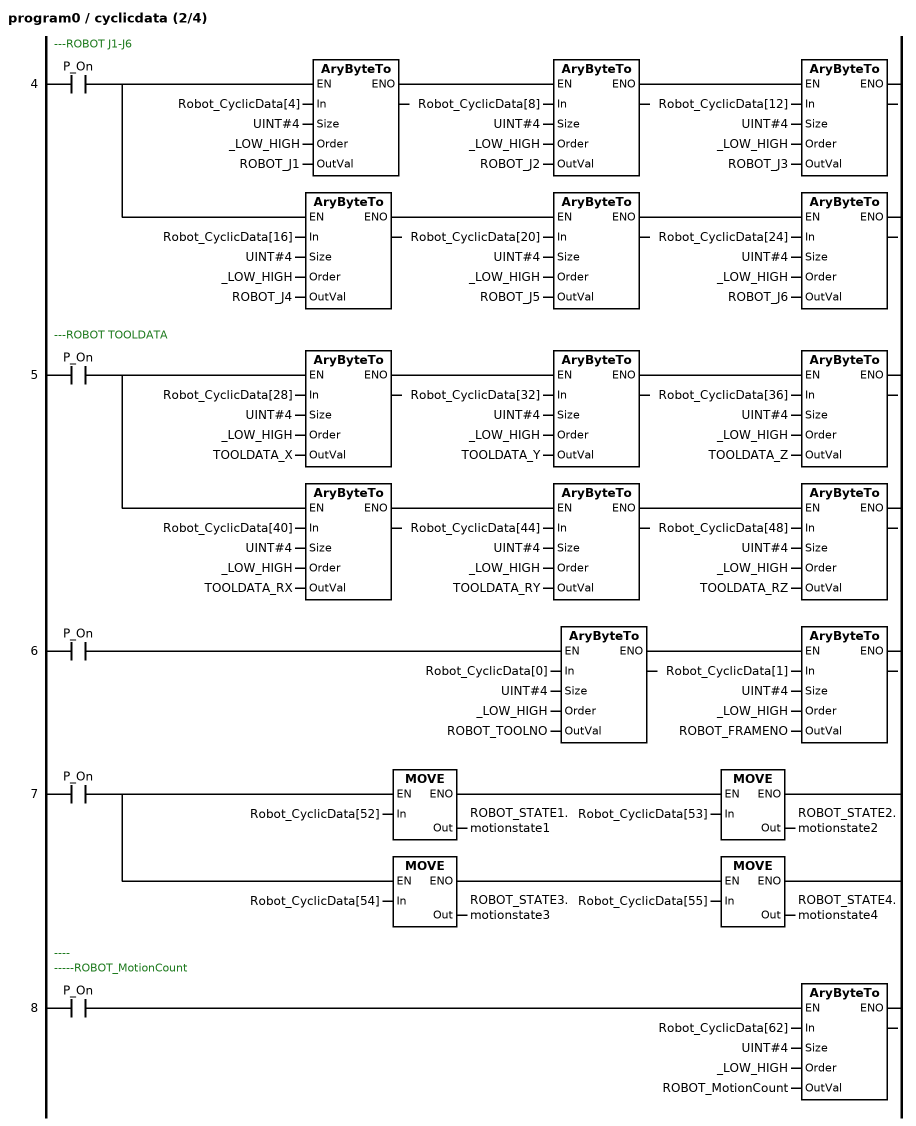
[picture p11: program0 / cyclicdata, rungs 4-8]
(* Rung 4: ---ROBOT J1-J6 *)
IF P_On THEN
    AryByteTo(In := Robot_CyclicData[4], Size := UINT#4, Order := _LOW_HIGH, OutVal := ROBOT_J1);
    AryByteTo(In := Robot_CyclicData[8], Size := UINT#4, Order := _LOW_HIGH, OutVal := ROBOT_J2);
    AryByteTo(In := Robot_CyclicData[12], Size := UINT#4, Order := _LOW_HIGH, OutVal := ROBOT_J3);
    AryByteTo(In := Robot_CyclicData[16], Size := UINT#4, Order := _LOW_HIGH, OutVal := ROBOT_J4);
    AryByteTo(In := Robot_CyclicData[20], Size := UINT#4, Order := _LOW_HIGH, OutVal := ROBOT_J5);
    AryByteTo(In := Robot_CyclicData[24], Size := UINT#4, Order := _LOW_HIGH, OutVal := ROBOT_J6);
END_IF;
(* Rung 5: ---ROBOT TOOLDATA *)
IF P_On THEN
    AryByteTo(In := Robot_CyclicData[28], Size := UINT#4, Order := _LOW_HIGH, OutVal := TOOLDATA_X);
    AryByteTo(In := Robot_CyclicData[32], Size := UINT#4, Order := _LOW_HIGH, OutVal := TOOLDATA_Y);
    AryByteTo(In := Robot_CyclicData[36], Size := UINT#4, Order := _LOW_HIGH, OutVal := TOOLDATA_Z);
    AryByteTo(In := Robot_CyclicData[40], Size := UINT#4, Order := _LOW_HIGH, OutVal := TOOLDATA_RX);
    AryByteTo(In := Robot_CyclicData[44], Size := UINT#4, Order := _LOW_HIGH, OutVal := TOOLDATA_RY);
    AryByteTo(In := Robot_CyclicData[48], Size := UINT#4, Order := _LOW_HIGH, OutVal := TOOLDATA_RZ);
END_IF;
(* Rung 6 *)
IF P_On THEN
    AryByteTo(In := Robot_CyclicData[0], Size := UINT#4, Order := _LOW_HIGH, OutVal := ROBOT_TOOLNO);
    AryByteTo(In := Robot_CyclicData[1], Size := UINT#4, Order := _LOW_HIGH, OutVal := ROBOT_FRAMENO);
END_IF;
(* Rung 7 *)
IF P_On THEN
    ROBOT_STATE1.motionstate1 := Robot_CyclicData[52];
    ROBOT_STATE2.motionstate2 := Robot_CyclicData[53];
    ROBOT_STATE3.motionstate3 := Robot_CyclicData[54];
    ROBOT_STATE4.motionstate4 := Robot_CyclicData[55];
END_IF;
(* Rung 8: ---- / -----ROBOT_MotionCount *)
IF P_On THEN
    AryByteTo(In := Robot_CyclicData[62], Size := UINT#4, Order := _LOW_HIGH, OutVal := ROBOT_MotionCount);
END_IF;

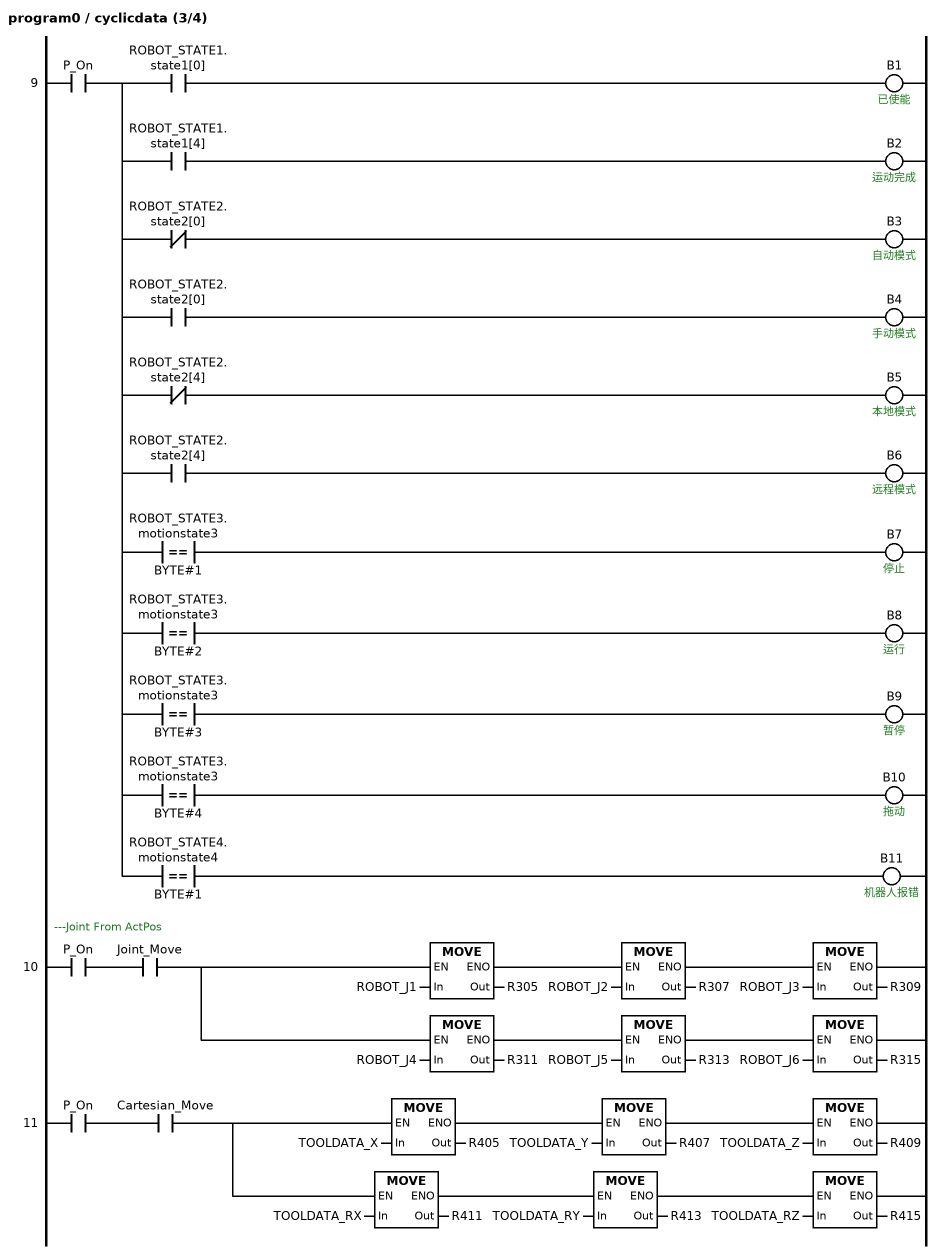
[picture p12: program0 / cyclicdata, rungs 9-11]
(* Rung 9 *)
B1 := P_On AND ROBOT_STATE1.state1[0];
B2 := P_On AND ROBOT_STATE1.state1[4];
B3 := P_On AND NOT ROBOT_STATE2.state2[0];
B4 := P_On AND ROBOT_STATE2.state2[0];
B5 := P_On AND NOT ROBOT_STATE2.state2[4];
B6 := P_On AND ROBOT_STATE2.state2[4];
B7 := P_On AND (ROBOT_STATE3.motionstate3 = BYTE#1);
B8 := P_On AND (ROBOT_STATE3.motionstate3 = BYTE#2);
B9 := P_On AND (ROBOT_STATE3.motionstate3 = BYTE#3);
B10 := P_On AND (ROBOT_STATE3.motionstate3 = BYTE#4);
B11 := P_On AND (ROBOT_STATE4.motionstate4 = BYTE#1);
(* Rung 10: ---Joint From ActPos *)
IF P_On AND Joint_Move THEN
    R305 := ROBOT_J1;
    R307 := ROBOT_J2;
    R309 := ROBOT_J3;
    R311 := ROBOT_J4;
    R313 := ROBOT_J5;
    R315 := ROBOT_J6;
END_IF;
(* Rung 11 *)
IF P_On AND Cartesian_Move THEN
    R405 := TOOLDATA_X;
    R407 := TOOLDATA_Y;
    R409 := TOOLDATA_Z;
    R411 := TOOLDATA_RX;
    R413 := TOOLDATA_RY;
    R415 := TOOLDATA_RZ;
END_IF;

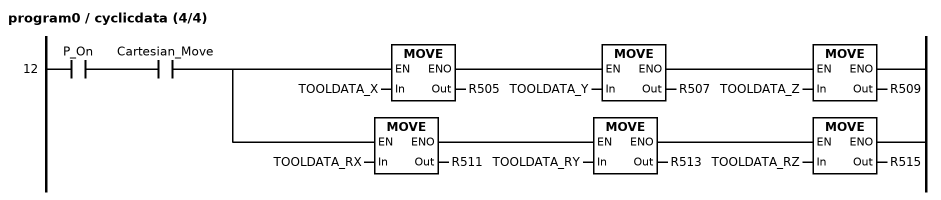
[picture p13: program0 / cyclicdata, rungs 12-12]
(* Rung 12 *)
IF P_On AND Cartesian_Move THEN
    R505 := TOOLDATA_X;
    R507 := TOOLDATA_Y;
    R509 := TOOLDATA_Z;
    R511 := TOOLDATA_RX;
    R513 := TOOLDATA_RY;
    R515 := TOOLDATA_RZ;
END_IF;

(* Section Section0: ladder, written here as Structured Text *)

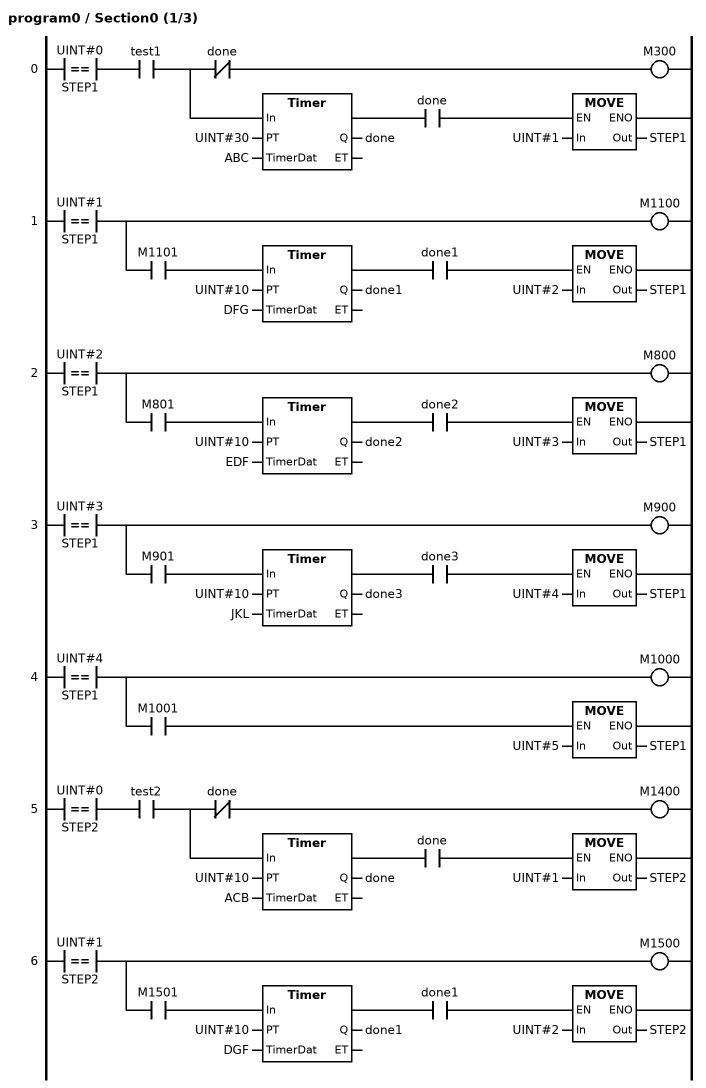
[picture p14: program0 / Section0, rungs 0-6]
(* Rung 0 *)
M300 := (UINT#0 = STEP1) AND test1 AND NOT done;
_p29 := (UINT#0 = STEP1) AND test1;
_t28 := Timer(In := _p29, PT := UINT#30, TimerDat := ABC, Q => done);
IF _t28 AND done THEN STEP1 := UINT#1; END_IF;
(* Rung 1 *)
M1100 := UINT#1 = STEP1;
_p31 := (UINT#1 = STEP1) AND M1101;
_t30 := Timer(In := _p31, PT := UINT#10, TimerDat := DFG, Q => done1);
IF _t30 AND done1 THEN STEP1 := UINT#2; END_IF;
(* Rung 2 *)
M800 := UINT#2 = STEP1;
_p33 := (UINT#2 = STEP1) AND M801;
_t32 := Timer(In := _p33, PT := UINT#10, TimerDat := EDF, Q => done2);
IF _t32 AND done2 THEN STEP1 := UINT#3; END_IF;
(* Rung 3 *)
M900 := UINT#3 = STEP1;
_p35 := (UINT#3 = STEP1) AND M901;
_t34 := Timer(In := _p35, PT := UINT#10, TimerDat := JKL, Q => done3);
IF _t34 AND done3 THEN STEP1 := UINT#4; END_IF;
(* Rung 4 *)
M1000 := UINT#4 = STEP1;
IF (UINT#4 = STEP1) AND M1001 THEN STEP1 := UINT#5; END_IF;
(* Rung 5 *)
M1400 := (UINT#0 = STEP2) AND test2 AND NOT done;
_p37 := (UINT#0 = STEP2) AND test2;
_t36 := Timer(In := _p37, PT := UINT#10, TimerDat := ACB, Q => done);
IF _t36 AND done THEN STEP2 := UINT#1; END_IF;
(* Rung 6 *)
M1500 := UINT#1 = STEP2;
_p39 := (UINT#1 = STEP2) AND M1501;
_t38 := Timer(In := _p39, PT := UINT#10, TimerDat := DGF, Q => done1);
IF _t38 AND done1 THEN STEP2 := UINT#2; END_IF;

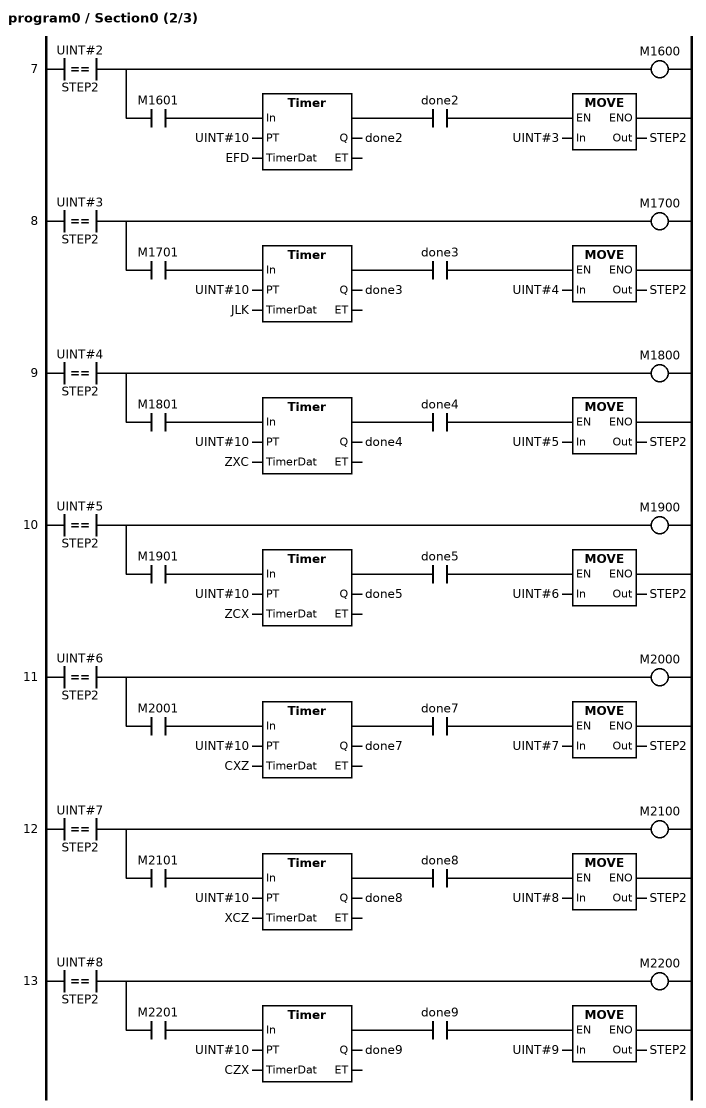
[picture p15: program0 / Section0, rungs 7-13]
(* Rung 7 *)
M1600 := UINT#2 = STEP2;
_p41 := (UINT#2 = STEP2) AND M1601;
_t40 := Timer(In := _p41, PT := UINT#10, TimerDat := EFD, Q => done2);
IF _t40 AND done2 THEN STEP2 := UINT#3; END_IF;
(* Rung 8 *)
M1700 := UINT#3 = STEP2;
_p43 := (UINT#3 = STEP2) AND M1701;
_t42 := Timer(In := _p43, PT := UINT#10, TimerDat := JLK, Q => done3);
IF _t42 AND done3 THEN STEP2 := UINT#4; END_IF;
(* Rung 9 *)
M1800 := UINT#4 = STEP2;
_p45 := (UINT#4 = STEP2) AND M1801;
_t44 := Timer(In := _p45, PT := UINT#10, TimerDat := ZXC, Q => done4);
IF _t44 AND done4 THEN STEP2 := UINT#5; END_IF;
(* Rung 10 *)
M1900 := UINT#5 = STEP2;
_p47 := (UINT#5 = STEP2) AND M1901;
_t46 := Timer(In := _p47, PT := UINT#10, TimerDat := ZCX, Q => done5);
IF _t46 AND done5 THEN STEP2 := UINT#6; END_IF;
(* Rung 11 *)
M2000 := UINT#6 = STEP2;
_p49 := (UINT#6 = STEP2) AND M2001;
_t48 := Timer(In := _p49, PT := UINT#10, TimerDat := CXZ, Q => done7);
IF _t48 AND done7 THEN STEP2 := UINT#7; END_IF;
(* Rung 12 *)
M2100 := UINT#7 = STEP2;
_p51 := (UINT#7 = STEP2) AND M2101;
_t50 := Timer(In := _p51, PT := UINT#10, TimerDat := XCZ, Q => done8);
IF _t50 AND done8 THEN STEP2 := UINT#8; END_IF;
(* Rung 13 *)
M2200 := UINT#8 = STEP2;
_p53 := (UINT#8 = STEP2) AND M2201;
_t52 := Timer(In := _p53, PT := UINT#10, TimerDat := CZX, Q => done9);
IF _t52 AND done9 THEN STEP2 := UINT#9; END_IF;

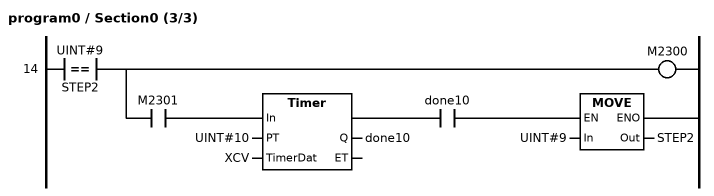
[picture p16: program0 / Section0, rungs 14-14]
(* Rung 14 *)
M2300 := UINT#9 = STEP2;
_p55 := (UINT#9 = STEP2) AND M2301;
_t54 := Timer(In := _p55, PT := UINT#10, TimerDat := XCV, Q => done10);
IF _t54 AND done10 THEN STEP2 := UINT#9; END_IF;
END_PROGRAM

FUNCTION_BLOCK RC_EnableRobot
VAR
    CMDLength : BYTE;
    CMDPayLoad : BYTE;
    CMD : UINT;
END_VAR
VAR_INPUT
    Enable : BOOL;
END_VAR
VAR_OUTPUT
    Status : BOOL;
    Busy : BOOL;
    Error : BOOL;
    ErrorID : UINT;
END_VAR
VAR_EXTERNAL
    RobotCMD : UINT;
    RobotCMDLength : BYTE;
    RobotCMDState : BYTE;
    M1 : BOOL;
    M2 : BOOL;
    EnableState : BOOL;
    Robot_CMDHeader : ARRAY[0..9] OF BYTE;
    Robot_Header : ARRAY[0..5] OF BYTE;
    M0 : BOOL;
    Robot_CMDPayload : ARRAY[0..119] OF BYTE;
    PLC_CMDHeader : ARRAY[0..9] OF BYTE;
    PLC_Header : ARRAY[0..5] OF BYTE;
    PLC_CMDPayload : ARRAY[0..238] OF BYTE;
    Robot_CyclicData : ARRAY[0..118] OF BYTE;
    EIP_OUT : ARRAY[0..255] OF BYTE;
    B1 : BOOL;
END_VAR
VAR
    _e1 : R_TRIG;
    _e2 : F_TRIG;
    _e3 : R_TRIG;
    _e4 : F_TRIG;
    _e5 : R_TRIG;
    _e6 : F_TRIG;
    _e7 : R_TRIG;
END_VAR
(* ladder, written here as Structured Text *)

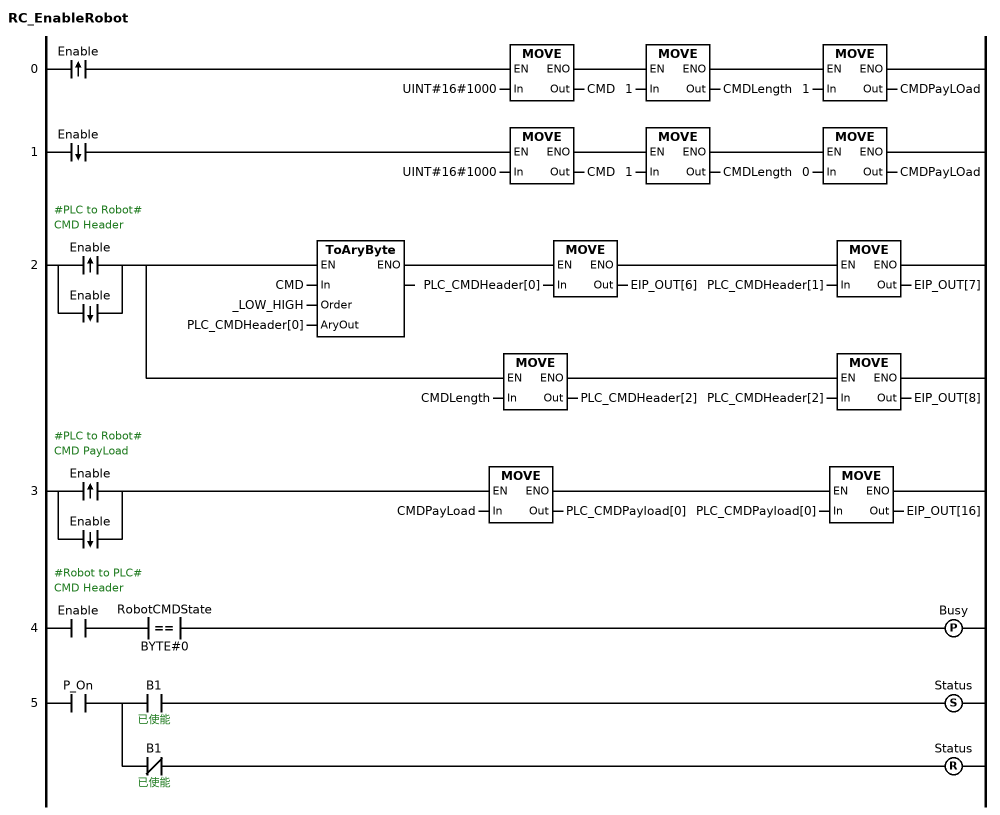
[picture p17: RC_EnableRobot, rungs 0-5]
(* Rung 0 *)
_e1(CLK := Enable);
IF _e1.Q THEN
    CMD := UINT#16#1000;
    CMDLength := 1;
    CMDPayLOad := 1;
END_IF;
(* Rung 1 *)
_e2(CLK := Enable);
IF _e2.Q THEN
    CMD := UINT#16#1000;
    CMDLength := 1;
    CMDPayLOad := 0;
END_IF;
(* Rung 2: #PLC to Robot# / CMD Header *)
_e3(CLK := Enable);
_e4(CLK := Enable);
IF _e3.Q OR _e4.Q THEN
    ToAryByte(In := CMD, Order := _LOW_HIGH, AryOut := PLC_CMDHeader[0]);
    EIP_OUT[6] := PLC_CMDHeader[0];
    EIP_OUT[7] := PLC_CMDHeader[1];
    PLC_CMDHeader[2] := CMDLength;
    EIP_OUT[8] := PLC_CMDHeader[2];
END_IF;
(* Rung 3: #PLC to Robot# / CMD PayLoad *)
_e5(CLK := Enable);
_e6(CLK := Enable);
IF _e5.Q OR _e6.Q THEN
    PLC_CMDPayload[0] := CMDPayLoad;
    EIP_OUT[16] := PLC_CMDPayload[0];
END_IF;
(* Rung 4: #Robot to PLC# / CMD Header *)
_e7(CLK := Enable AND (RobotCMDState = BYTE#0));
Busy := _e7.Q;
(* Rung 5 *)
IF P_On AND B1 THEN Status := TRUE; END_IF;
IF P_On AND NOT B1 THEN Status := FALSE; END_IF;
END_FUNCTION_BLOCK

FUNCTION_BLOCK RC_WriteToolData
VAR
    CMD : UINT;
    CMDLength : BYTE;
END_VAR
VAR_INPUT
    Execute : BOOL;
    ID : BYTE;
    LoadNo : BYTE;
    ToolNO : BYTE;
    X : REAL;
    Y : REAL;
    Z : REAL;
    RX : REAL;
    RY : REAL;
    RZ : REAL;
END_VAR
VAR_OUTPUT
    Done : BOOL;
    Busy : BOOL;
    Error : BOOL;
    ErrorID : UINT;
END_VAR
VAR_EXTERNAL
    M200 : BOOL;
    Robot_CMDPayload : ARRAY[0..119] OF BYTE;
    RobotCMD : UINT;
    RobotCMDLength : BYTE;
    RobotCMDState : BYTE;
    R205 : REAL;
    R207 : REAL;
    R209 : REAL;
    R211 : REAL;
    R213 : REAL;
    R215 : REAL;
    PLC_CMDHeader : ARRAY[0..9] OF BYTE;
    PLC_Header : ARRAY[0..5] OF BYTE;
    PLC_CMDPayload : ARRAY[0..238] OF BYTE;
    EIP_OUT : ARRAY[0..255] OF BYTE;
END_VAR
(* ladder, written here as Structured Text *)

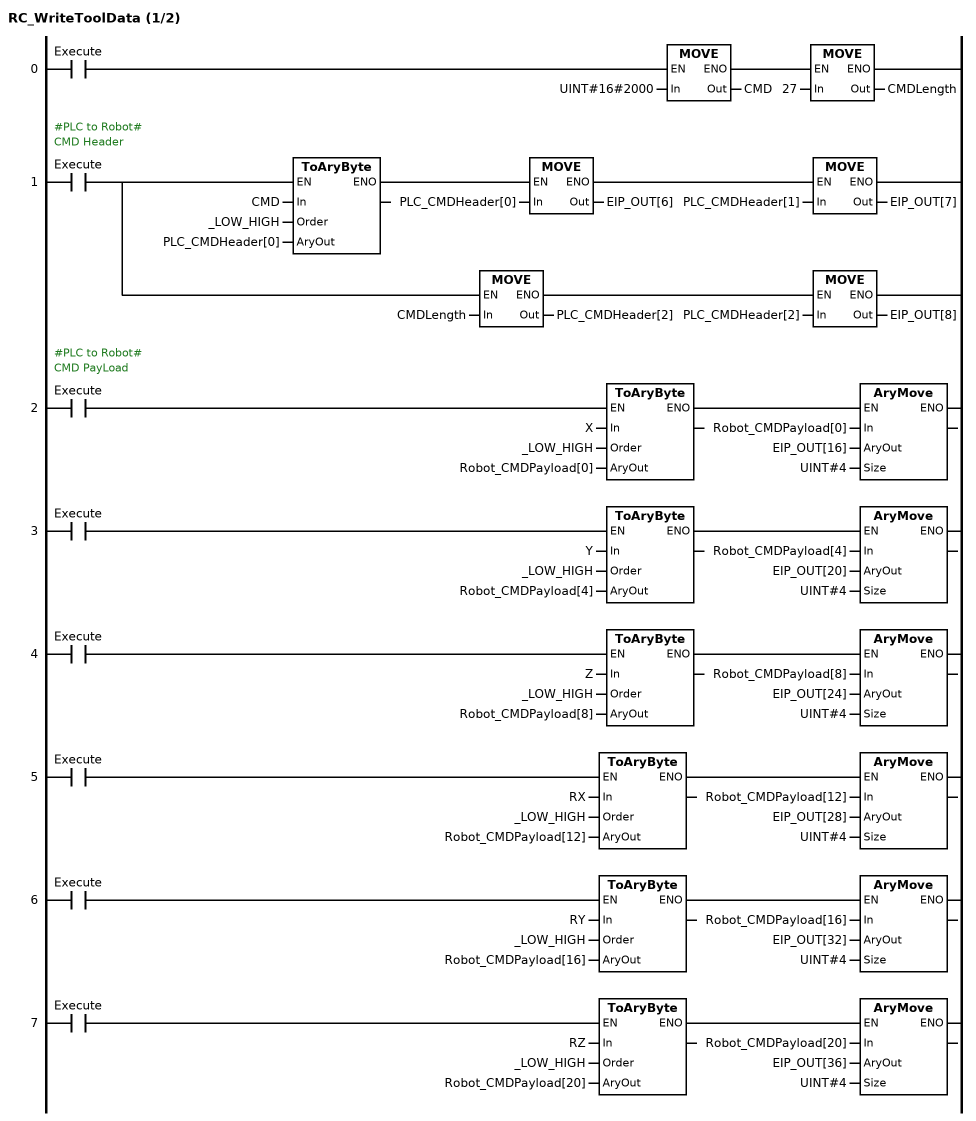
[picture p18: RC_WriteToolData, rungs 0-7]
(* Rung 0 *)
IF Execute THEN
    CMD := UINT#16#2000;
    CMDLength := 27;
END_IF;
(* Rung 1: #PLC to Robot# / CMD Header *)
IF Execute THEN
    ToAryByte(In := CMD, Order := _LOW_HIGH, AryOut := PLC_CMDHeader[0]);
    EIP_OUT[6] := PLC_CMDHeader[0];
    EIP_OUT[7] := PLC_CMDHeader[1];
    PLC_CMDHeader[2] := CMDLength;
    EIP_OUT[8] := PLC_CMDHeader[2];
END_IF;
(* Rung 2: #PLC to Robot# / CMD PayLoad *)
IF Execute THEN
    ToAryByte(In := X, Order := _LOW_HIGH, AryOut := Robot_CMDPayload[0]);
    AryMove(In := Robot_CMDPayload[0], AryOut := EIP_OUT[16], Size := UINT#4);
END_IF;
(* Rung 3 *)
IF Execute THEN
    ToAryByte(In := Y, Order := _LOW_HIGH, AryOut := Robot_CMDPayload[4]);
    AryMove(In := Robot_CMDPayload[4], AryOut := EIP_OUT[20], Size := UINT#4);
END_IF;
(* Rung 4 *)
IF Execute THEN
    ToAryByte(In := Z, Order := _LOW_HIGH, AryOut := Robot_CMDPayload[8]);
    AryMove(In := Robot_CMDPayload[8], AryOut := EIP_OUT[24], Size := UINT#4);
END_IF;
(* Rung 5 *)
IF Execute THEN
    ToAryByte(In := RX, Order := _LOW_HIGH, AryOut := Robot_CMDPayload[12]);
    AryMove(In := Robot_CMDPayload[12], AryOut := EIP_OUT[28], Size := UINT#4);
END_IF;
(* Rung 6 *)
IF Execute THEN
    ToAryByte(In := RY, Order := _LOW_HIGH, AryOut := Robot_CMDPayload[16]);
    AryMove(In := Robot_CMDPayload[16], AryOut := EIP_OUT[32], Size := UINT#4);
END_IF;
(* Rung 7 *)
IF Execute THEN
    ToAryByte(In := RZ, Order := _LOW_HIGH, AryOut := Robot_CMDPayload[20]);
    AryMove(In := Robot_CMDPayload[20], AryOut := EIP_OUT[36], Size := UINT#4);
END_IF;

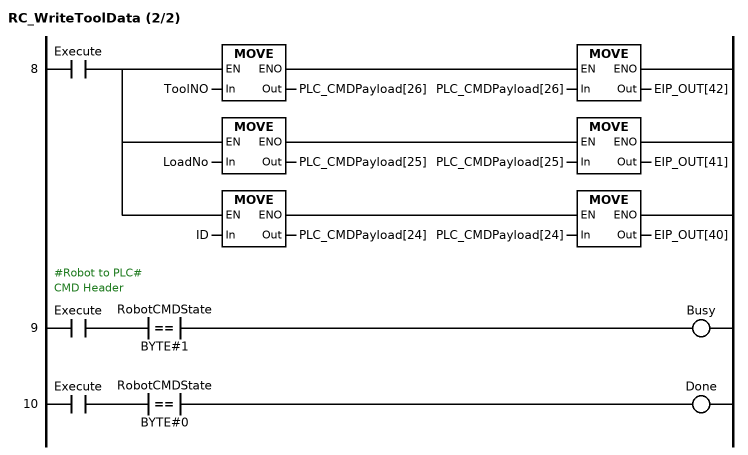
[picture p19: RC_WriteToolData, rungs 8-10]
(* Rung 8 *)
IF Execute THEN
    PLC_CMDPayload[26] := ToolNO;
    EIP_OUT[42] := PLC_CMDPayload[26];
    PLC_CMDPayload[25] := LoadNo;
    EIP_OUT[41] := PLC_CMDPayload[25];
    PLC_CMDPayload[24] := ID;
    EIP_OUT[40] := PLC_CMDPayload[24];
END_IF;
(* Rung 9: #Robot to PLC# / CMD Header *)
Busy := Execute AND (RobotCMDState = BYTE#1);
(* Rung 10 *)
Done := Execute AND (RobotCMDState = BYTE#0);
END_FUNCTION_BLOCK

FUNCTION_BLOCK RC_ReadToolData
VAR
    CMD : UINT;
    CMDLength : BYTE;
    CMDPayLoad : BYTE;
END_VAR
VAR_INPUT
    Execute : BOOL;
    ToolNO : BYTE;
END_VAR
VAR_OUTPUT
    Done : BOOL;
    Busy : BOOL;
    ID : BYTE;
    LoadNo : BYTE;
    ToolNo_return : BYTE;
    X_Return : REAL;
    Y_Return : REAL;
    Z_Return : REAL;
    RX_Return : REAL;
    RY_Return : REAL;
    RZ_Return : REAL;
    Error : BOOL;
    ErrorID : UINT;
END_VAR
VAR_EXTERNAL
    Robot_CMDPayload : ARRAY[0..119] OF BYTE;
    RobotCMDLength : BYTE;
    RobotCMDState : BYTE;
    RobotCMD : UINT;
    R160 : REAL;
    R162 : REAL;
    Robot_CyclicData : ARRAY[0..118] OF BYTE;
    Robot_CMDHeader : ARRAY[0..9] OF BYTE;
    PLC_CMDHeader : ARRAY[0..9] OF BYTE;
    PLC_Header : ARRAY[0..5] OF BYTE;
    PLC_CMDPayload : ARRAY[0..238] OF BYTE;
    EIP_OUT : ARRAY[0..255] OF BYTE;
END_VAR
(* ladder, written here as Structured Text *)

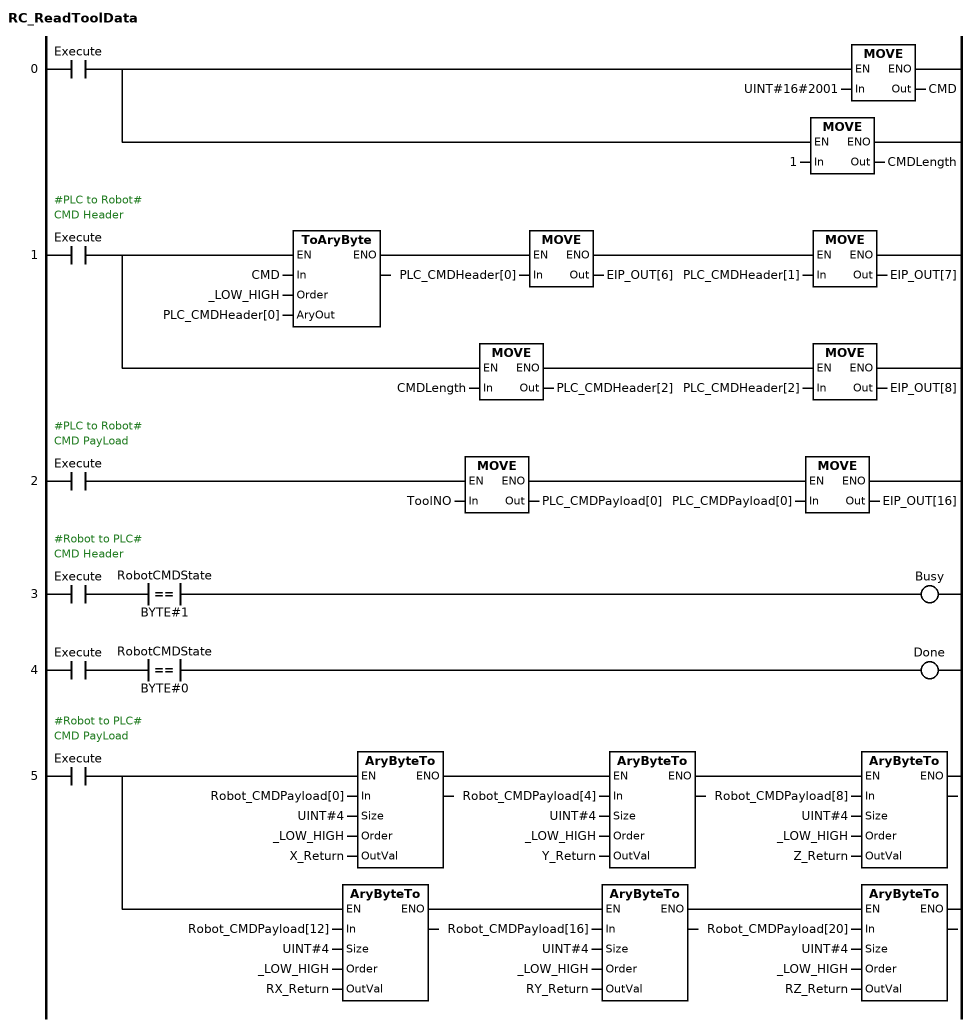
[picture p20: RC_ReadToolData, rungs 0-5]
(* Rung 0 *)
IF Execute THEN
    CMD := UINT#16#2001;
    CMDLength := 1;
END_IF;
(* Rung 1: #PLC to Robot# / CMD Header *)
IF Execute THEN
    ToAryByte(In := CMD, Order := _LOW_HIGH, AryOut := PLC_CMDHeader[0]);
    EIP_OUT[6] := PLC_CMDHeader[0];
    EIP_OUT[7] := PLC_CMDHeader[1];
    PLC_CMDHeader[2] := CMDLength;
    EIP_OUT[8] := PLC_CMDHeader[2];
END_IF;
(* Rung 2: #PLC to Robot# / CMD PayLoad *)
IF Execute THEN
    PLC_CMDPayload[0] := ToolNO;
    EIP_OUT[16] := PLC_CMDPayload[0];
END_IF;
(* Rung 3: #Robot to PLC# / CMD Header *)
Busy := Execute AND (RobotCMDState = BYTE#1);
(* Rung 4 *)
Done := Execute AND (RobotCMDState = BYTE#0);
(* Rung 5: #Robot to PLC# / CMD PayLoad *)
IF Execute THEN
    AryByteTo(In := Robot_CMDPayload[0], Size := UINT#4, Order := _LOW_HIGH, OutVal := X_Return);
    AryByteTo(In := Robot_CMDPayload[4], Size := UINT#4, Order := _LOW_HIGH, OutVal := Y_Return);
    AryByteTo(In := Robot_CMDPayload[8], Size := UINT#4, Order := _LOW_HIGH, OutVal := Z_Return);
    AryByteTo(In := Robot_CMDPayload[12], Size := UINT#4, Order := _LOW_HIGH, OutVal := RX_Return);
    AryByteTo(In := Robot_CMDPayload[16], Size := UINT#4, Order := _LOW_HIGH, OutVal := RY_Return);
    AryByteTo(In := Robot_CMDPayload[20], Size := UINT#4, Order := _LOW_HIGH, OutVal := RZ_Return);
END_IF;
END_FUNCTION_BLOCK

FUNCTION_BLOCK RC_MoveAxesAbsolute
VAR
    CMD : UINT;
    CMDLength : BYTE;
    BlendingParameter : ARRAY[0..7] OF BYTE;
    AbortingMode : BYTE;
    BlendingMode : BYTE;
    Cmdid : BYTE;
END_VAR
VAR_INPUT
    Execute : BOOL;
    ToolNo : BYTE;
    velRate : REAL;
    accRate : REAL;
    J1 : REAL;
    J2 : REAL;
    J3 : REAL;
    J4 : REAL;
    J5 : REAL;
    J6 : REAL;
END_VAR
VAR_OUTPUT
    Done : BOOL;
    Busy : BOOL;
    Active : BOOL;
    Aborted : BOOL;
    Interrupt : BOOL;
    Error : BOOL;
    ErrorID : UINT;
END_VAR
VAR_EXTERNAL
    RobotCMDLength : BYTE;
    RobotCMDState : BYTE;
    RobotCMD : UINT;
    Robot_CyclicData : ARRAY[0..118] OF BYTE;
    Robot_CMDHeader : ARRAY[0..9] OF BYTE;
    Robot_CMDPayload : ARRAY[0..119] OF BYTE;
    M300 : BOOL;
    PLC_CMDHeader : ARRAY[0..9] OF BYTE;
    PLC_Header : ARRAY[0..5] OF BYTE;
    PLC_CMDPayload : ARRAY[0..238] OF BYTE;
    EIP_OUT : ARRAY[0..255] OF BYTE;
    B8 : BOOL;
    B2 : BOOL;
END_VAR
VAR
    _e1 : R_TRIG;
    _e2 : R_TRIG;
    _e3 : R_TRIG;
    _e4 : R_TRIG;
    _e5 : R_TRIG;
    _e6 : R_TRIG;
    _e7 : R_TRIG;
    _e8 : R_TRIG;
    _e9 : R_TRIG;
    _e10 : R_TRIG;
    _e11 : R_TRIG;
END_VAR
(* ladder, written here as Structured Text *)

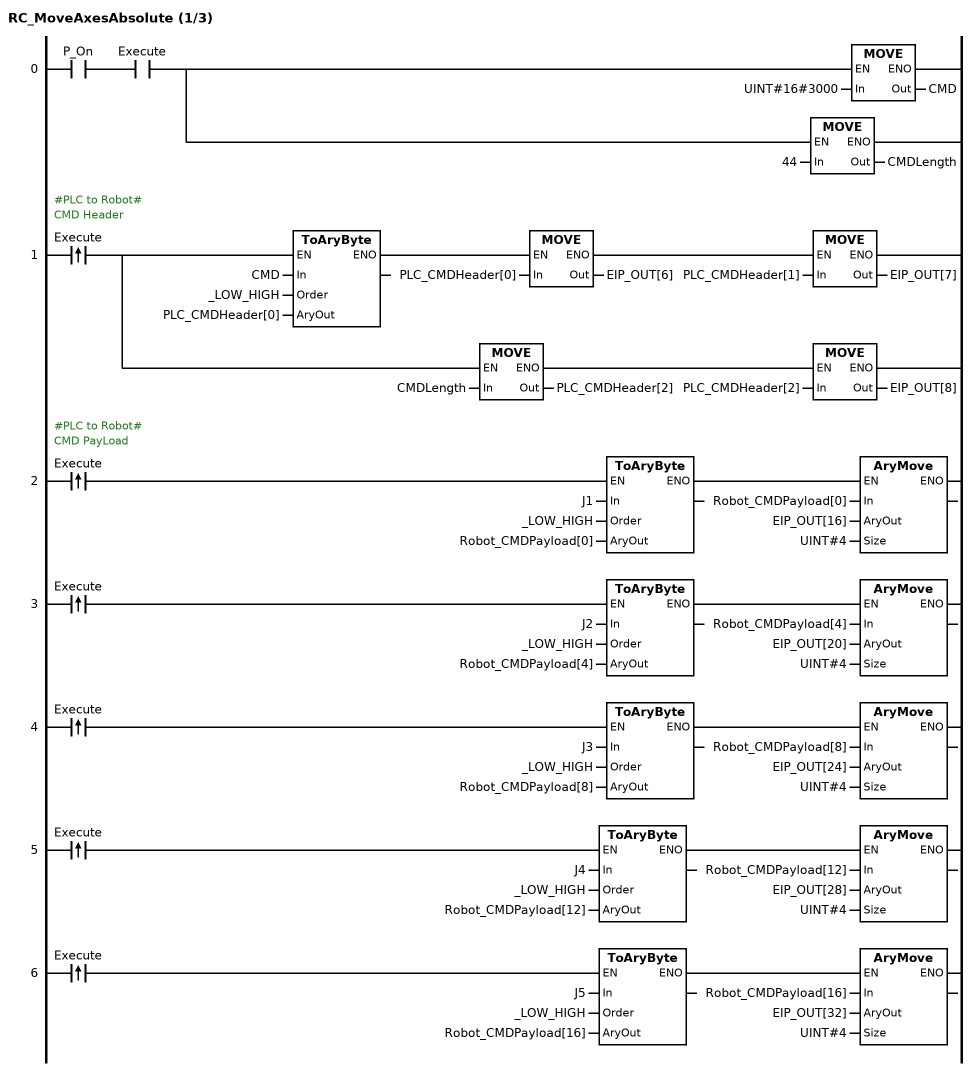
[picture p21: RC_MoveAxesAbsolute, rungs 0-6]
(* Rung 0 *)
IF P_On AND Execute THEN
    CMD := UINT#16#3000;
    CMDLength := 44;
END_IF;
(* Rung 1: #PLC to Robot# / CMD Header *)
_e1(CLK := Execute);
IF _e1.Q THEN
    ToAryByte(In := CMD, Order := _LOW_HIGH, AryOut := PLC_CMDHeader[0]);
    EIP_OUT[6] := PLC_CMDHeader[0];
    EIP_OUT[7] := PLC_CMDHeader[1];
    PLC_CMDHeader[2] := CMDLength;
    EIP_OUT[8] := PLC_CMDHeader[2];
END_IF;
(* Rung 2: #PLC to Robot# / CMD PayLoad *)
_e2(CLK := Execute);
IF _e2.Q THEN
    ToAryByte(In := J1, Order := _LOW_HIGH, AryOut := Robot_CMDPayload[0]);
    AryMove(In := Robot_CMDPayload[0], AryOut := EIP_OUT[16], Size := UINT#4);
END_IF;
(* Rung 3 *)
_e3(CLK := Execute);
IF _e3.Q THEN
    ToAryByte(In := J2, Order := _LOW_HIGH, AryOut := Robot_CMDPayload[4]);
    AryMove(In := Robot_CMDPayload[4], AryOut := EIP_OUT[20], Size := UINT#4);
END_IF;
(* Rung 4 *)
_e4(CLK := Execute);
IF _e4.Q THEN
    ToAryByte(In := J3, Order := _LOW_HIGH, AryOut := Robot_CMDPayload[8]);
    AryMove(In := Robot_CMDPayload[8], AryOut := EIP_OUT[24], Size := UINT#4);
END_IF;
(* Rung 5 *)
_e5(CLK := Execute);
IF _e5.Q THEN
    ToAryByte(In := J4, Order := _LOW_HIGH, AryOut := Robot_CMDPayload[12]);
    AryMove(In := Robot_CMDPayload[12], AryOut := EIP_OUT[28], Size := UINT#4);
END_IF;
(* Rung 6 *)
_e6(CLK := Execute);
IF _e6.Q THEN
    ToAryByte(In := J5, Order := _LOW_HIGH, AryOut := Robot_CMDPayload[16]);
    AryMove(In := Robot_CMDPayload[16], AryOut := EIP_OUT[32], Size := UINT#4);
END_IF;

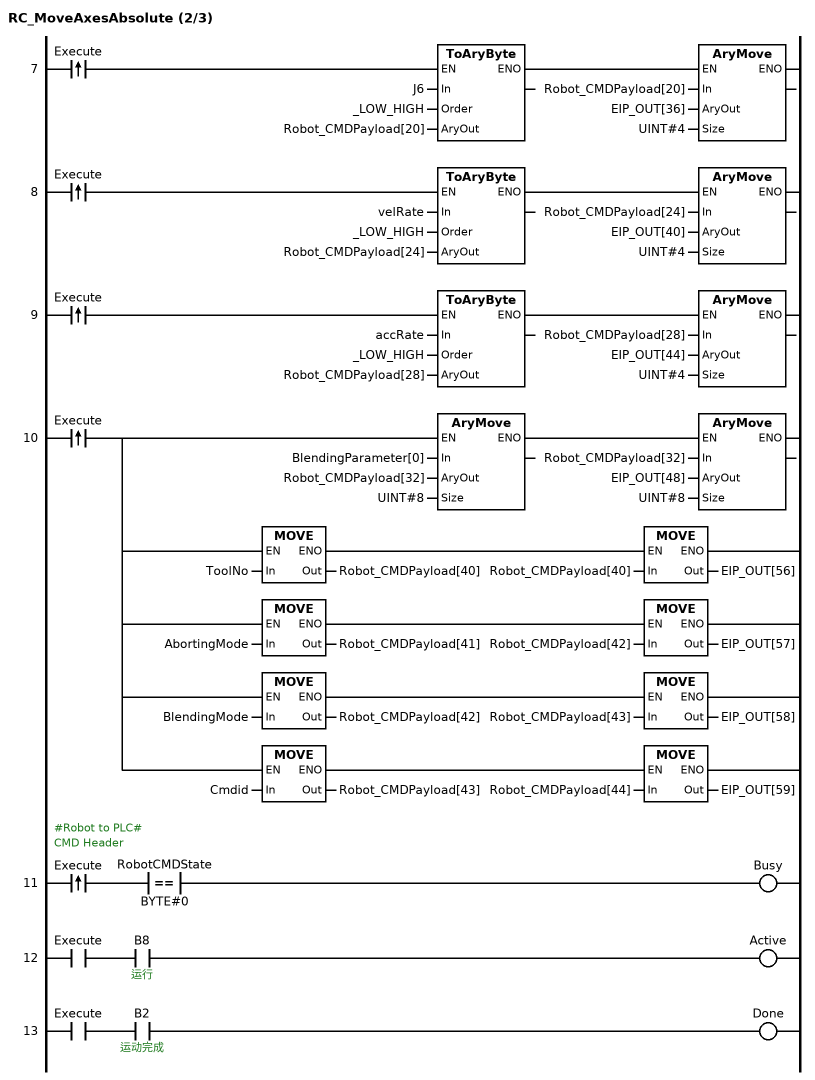
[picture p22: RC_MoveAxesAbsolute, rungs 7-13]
(* Rung 7 *)
_e7(CLK := Execute);
IF _e7.Q THEN
    ToAryByte(In := J6, Order := _LOW_HIGH, AryOut := Robot_CMDPayload[20]);
    AryMove(In := Robot_CMDPayload[20], AryOut := EIP_OUT[36], Size := UINT#4);
END_IF;
(* Rung 8 *)
_e8(CLK := Execute);
IF _e8.Q THEN
    ToAryByte(In := velRate, Order := _LOW_HIGH, AryOut := Robot_CMDPayload[24]);
    AryMove(In := Robot_CMDPayload[24], AryOut := EIP_OUT[40], Size := UINT#4);
END_IF;
(* Rung 9 *)
_e9(CLK := Execute);
IF _e9.Q THEN
    ToAryByte(In := accRate, Order := _LOW_HIGH, AryOut := Robot_CMDPayload[28]);
    AryMove(In := Robot_CMDPayload[28], AryOut := EIP_OUT[44], Size := UINT#4);
END_IF;
(* Rung 10 *)
_e10(CLK := Execute);
IF _e10.Q THEN
    AryMove(In := BlendingParameter[0], AryOut := Robot_CMDPayload[32], Size := UINT#8);
    AryMove(In := Robot_CMDPayload[32], AryOut := EIP_OUT[48], Size := UINT#8);
    Robot_CMDPayload[40] := ToolNo;
    EIP_OUT[56] := Robot_CMDPayload[40];
    Robot_CMDPayload[41] := AbortingMode;
    EIP_OUT[57] := Robot_CMDPayload[42];
    Robot_CMDPayload[42] := BlendingMode;
    EIP_OUT[58] := Robot_CMDPayload[43];
    Robot_CMDPayload[43] := Cmdid;
    EIP_OUT[59] := Robot_CMDPayload[44];
END_IF;
(* Rung 11: #Robot to PLC# / CMD Header *)
_e11(CLK := Execute);
Busy := _e11.Q AND (RobotCMDState = BYTE#0);
(* Rung 12 *)
Active := Execute AND B8;
(* Rung 13 *)
Done := Execute AND B2;

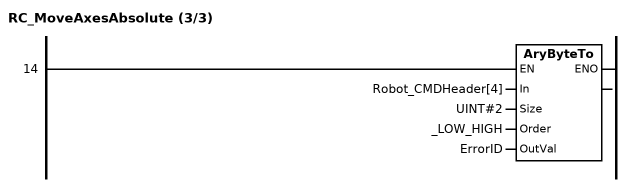
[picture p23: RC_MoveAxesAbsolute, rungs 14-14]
(* Rung 14 *)
AryByteTo(In := Robot_CMDHeader[4], Size := UINT#2, Order := _LOW_HIGH, OutVal := ErrorID);
END_FUNCTION_BLOCK

FUNCTION_BLOCK RC_MoveLinearAbsolute
VAR
    CMDLength : BYTE;
    CMD : UINT;
END_VAR
VAR_INPUT
    Execute : BOOL;
    ToolNo : BYTE;
    velRate : REAL;
    accRate : REAL;
    X : REAL;
    Y : REAL;
    Z : REAL;
    RX : REAL;
    RY : REAL;
    RZ : REAL;
END_VAR
VAR_OUTPUT
    Done : BOOL;
    Busy : BOOL;
    Active : BOOL;
    Aborted : BOOL;
    Interrupt : BOOL;
    Error : BOOL;
    ErrorID : UINT;
END_VAR
VAR_EXTERNAL
    RobotCMD : UINT;
    RobotCMDLength : BYTE;
    RobotCMDState : BYTE;
    Robot_CMDPayload : ARRAY[0..119] OF BYTE;
    M200 : BOOL;
    M400 : BOOL;
    PLC_CMDHeader : ARRAY[0..9] OF BYTE;
    PLC_Header : ARRAY[0..5] OF BYTE;
    PLC_CMDPayload : ARRAY[0..238] OF BYTE;
    EIP_OUT : ARRAY[0..255] OF BYTE;
    B8 : BOOL;
    B2 : BOOL;
END_VAR
(* ladder, written here as Structured Text *)

(* Rung 0 *)
IF Execute THEN
    CMD := UINT#16#3001;
    CMDLength := 54;
END_IF;
(* Rung 1: #PLC to Robot# / CMD Header *)
IF Execute THEN
    ToAryByte(In := CMD, Order := _LOW_HIGH, AryOut := PLC_CMDHeader[0]);
    EIP_OUT[6] := PLC_CMDHeader[0];
    EIP_OUT[7] := PLC_CMDHeader[1];
    PLC_CMDHeader[2] := CMDLength;
    EIP_OUT[8] := PLC_CMDHeader[2];
END_IF;
(* Rung 2: #PLC to Robot# / CMD PayLoad *)
IF Execute THEN
    PLC_CMDPayload[40] := ToolNo;
    EIP_OUT[56] := PLC_CMDPayload[40];
END_IF;
(* Rung 3 *)
IF Execute THEN
    ToAryByte(In := X, Order := _LOW_HIGH, AryOut := Robot_CMDPayload[0]);
    AryMove(In := Robot_CMDPayload[0], AryOut := EIP_OUT[16], Size := UINT#4);
END_IF;
(* Rung 4 *)
IF Execute THEN
    ToAryByte(In := Y, Order := _LOW_HIGH, AryOut := Robot_CMDPayload[4]);
    AryMove(In := Robot_CMDPayload[4], AryOut := EIP_OUT[20], Size := UINT#4);
END_IF;
(* Rung 5 *)
IF Execute THEN
    ToAryByte(In := Z, Order := _LOW_HIGH, AryOut := Robot_CMDPayload[8]);
    AryMove(In := Robot_CMDPayload[8], AryOut := EIP_OUT[24], Size := UINT#4);
END_IF;
(* Rung 6 *)
IF Execute THEN
    ToAryByte(In := RX, Order := _LOW_HIGH, AryOut := Robot_CMDPayload[12]);
    AryMove(In := Robot_CMDPayload[12], AryOut := EIP_OUT[28], Size := UINT#4);
END_IF;
(* Rung 7 *)
IF Execute THEN
    ToAryByte(In := RY, Order := _LOW_HIGH, AryOut := Robot_CMDPayload[16]);
    AryMove(In := Robot_CMDPayload[16], AryOut := EIP_OUT[32], Size := UINT#4);
END_IF;

(* Rung 8 *)
IF Execute THEN
    ToAryByte(In := RZ, Order := _LOW_HIGH, AryOut := Robot_CMDPayload[20]);
    AryMove(In := Robot_CMDPayload[20], AryOut := EIP_OUT[36], Size := UINT#4);
END_IF;
(* Rung 9 *)
IF Execute THEN
    ToAryByte(In := velRate, Order := _LOW_HIGH, AryOut := Robot_CMDPayload[24]);
    AryMove(In := Robot_CMDPayload[24], AryOut := EIP_OUT[40], Size := UINT#4);
END_IF;
(* Rung 10 *)
IF Execute THEN
    ToAryByte(In := accRate, Order := _LOW_HIGH, AryOut := Robot_CMDPayload[28]);
    AryMove(In := Robot_CMDPayload[28], AryOut := EIP_OUT[44], Size := UINT#4);
END_IF;
(* Rung 11: #Robot to PLC# / CMD Header *)
Busy := Execute AND (RobotCMDState = BYTE#0);
(* Rung 12 *)
Active := Execute AND B8;
(* Rung 13 *)
Done := Execute AND B2;
END_FUNCTION_BLOCK

FUNCTION_BLOCK RC_MoveDirectAbsolute
VAR
    CMD : UINT;
    CMDLength : BYTE;
END_VAR
VAR_INPUT
    Execute : BOOL;
    ToolNo : BYTE;
    FrameNo : BYTE;
    velRate : REAL;
    accRate : REAL;
    X : REAL;
    Y : REAL;
    Z : REAL;
    RX : REAL;
    RY : REAL;
    RZ : REAL;
END_VAR
VAR_OUTPUT
    Done : BOOL;
    Busy : BOOL;
    Active : BOOL;
    Aborted : BOOL;
    Interrupt : BOOL;
    Error : BOOL;
    ErrorID : UINT;
END_VAR
VAR_EXTERNAL
    RobotCMD : UINT;
    RobotCMDLength : BYTE;
    RobotCMDState : BYTE;
    Robot_CMDPayload : ARRAY[0..119] OF BYTE;
    PLC_CMDHeader : ARRAY[0..9] OF BYTE;
    PLC_Header : ARRAY[0..5] OF BYTE;
    PLC_CMDPayload : ARRAY[0..238] OF BYTE;
    EIP_OUT : ARRAY[0..255] OF BYTE;
    B8 : BOOL;
    B2 : BOOL;
END_VAR
(* ladder, written here as Structured Text *)

(* Rung 0 *)
IF Execute THEN
    CMD := UINT#16#3002;
    CMDLength := 54;
END_IF;
(* Rung 1: #PLC to Robot# / CMD Header *)
IF Execute THEN
    ToAryByte(In := CMD, Order := _LOW_HIGH, AryOut := PLC_CMDHeader[0]);
    EIP_OUT[6] := PLC_CMDHeader[0];
    EIP_OUT[7] := PLC_CMDHeader[1];
    PLC_CMDHeader[2] := CMDLength;
    EIP_OUT[8] := PLC_CMDHeader[2];
END_IF;
(* Rung 2: #PLC to Robot# / CMD PayLoad *)
IF Execute THEN
    PLC_CMDPayload[40] := ToolNo;
    EIP_OUT[56] := PLC_CMDPayload[40];
    PLC_CMDPayload[41] := FrameNo;
    EIP_OUT[57] := PLC_CMDPayload[27];
END_IF;
(* Rung 3 *)
IF Execute THEN
    ToAryByte(In := X, Order := _LOW_HIGH, AryOut := Robot_CMDPayload[0]);
    AryMove(In := Robot_CMDPayload[0], AryOut := EIP_OUT[16], Size := UINT#4);
END_IF;
(* Rung 4 *)
IF Execute THEN
    ToAryByte(In := Y, Order := _LOW_HIGH, AryOut := Robot_CMDPayload[4]);
    AryMove(In := Robot_CMDPayload[4], AryOut := EIP_OUT[20], Size := UINT#4);
END_IF;
(* Rung 5 *)
IF Execute THEN
    ToAryByte(In := Z, Order := _LOW_HIGH, AryOut := Robot_CMDPayload[8]);
    AryMove(In := Robot_CMDPayload[8], AryOut := EIP_OUT[24], Size := UINT#4);
END_IF;
(* Rung 6 *)
IF Execute THEN
    ToAryByte(In := RX, Order := _LOW_HIGH, AryOut := Robot_CMDPayload[12]);
    AryMove(In := Robot_CMDPayload[12], AryOut := EIP_OUT[28], Size := UINT#4);
END_IF;

(* Rung 7 *)
IF Execute THEN
    ToAryByte(In := RY, Order := _LOW_HIGH, AryOut := Robot_CMDPayload[16]);
    AryMove(In := Robot_CMDPayload[16], AryOut := EIP_OUT[32], Size := UINT#4);
END_IF;
(* Rung 8 *)
IF Execute THEN
    ToAryByte(In := RZ, Order := _LOW_HIGH, AryOut := Robot_CMDPayload[20]);
    AryMove(In := Robot_CMDPayload[20], AryOut := EIP_OUT[36], Size := UINT#4);
END_IF;
(* Rung 9 *)
IF Execute THEN
    ToAryByte(In := velRate, Order := _LOW_HIGH, AryOut := Robot_CMDPayload[24]);
    AryMove(In := Robot_CMDPayload[24], AryOut := EIP_OUT[40], Size := UINT#4);
END_IF;
(* Rung 10 *)
IF Execute THEN
    ToAryByte(In := accRate, Order := _LOW_HIGH, AryOut := Robot_CMDPayload[28]);
    AryMove(In := Robot_CMDPayload[28], AryOut := EIP_OUT[44], Size := UINT#4);
END_IF;
(* Rung 11: #Robot to PLC# / CMD Header *)
Busy := Execute AND (RobotCMDState = BYTE#0);
(* Rung 12 *)
Active := Execute AND B8;
(* Rung 13 *)
Done := Execute AND B2;
END_FUNCTION_BLOCK

FUNCTION_BLOCK RC_GroupReset
VAR
    CMD : UINT;
    CMDLength : BYTE;
    CMDLength_Return : BYTE;
    CMD_Return : UINT;
END_VAR
VAR_INPUT
    Execute : BOOL;
END_VAR
VAR_OUTPUT
    Done : BOOL;
    Busy : BOOL;
    CommandBuffed : BOOL;
    Error : BOOL;
    ErrorID : UINT;
END_VAR
VAR_EXTERNAL
    PLC_CMDHeader : ARRAY[0..9] OF BYTE;
    EIP_OUT : ARRAY[0..255] OF BYTE;
    PLC_Header : ARRAY[0..5] OF BYTE;
    RobotCMDState : BYTE;
    Robot_CMDHeader : ARRAY[0..9] OF BYTE;
END_VAR
VAR
    _e1 : R_TRIG;
END_VAR
(* ladder, written here as Structured Text *)

(* Rung 0 *)
IF Execute THEN
    CMD := UINT#16#1001;
    CMDLength := 0;
END_IF;
(* Rung 1: #PLC to Robot# / CMD Header *)
IF Execute THEN
    ToAryByte(In := CMD, Order := _LOW_HIGH, AryOut := PLC_CMDHeader[0]);
    EIP_OUT[6] := PLC_CMDHeader[0];
    EIP_OUT[7] := PLC_CMDHeader[1];
    PLC_CMDHeader[2] := CMDLength;
    EIP_OUT[8] := PLC_CMDHeader[2];
END_IF;
(* Rung 2: #Robot to PLC# / CMD Header *)
_e1(CLK := Execute AND (RobotCMDState = BYTE#0));
Busy := _e1.Q;
Done := Execute AND (RobotCMDState = BYTE#0);
IF Execute THEN
    AryByteTo(In := Robot_CMDHeader[0], Size := UINT#2, Order := _LOW_HIGH, OutVal := CMD_Return);
    CMDLength_Return := Robot_CMDHeader[2];
END_IF;
END_FUNCTION_BLOCK

FUNCTION_BLOCK RC_GroupStop
VAR
    CMD : UINT;
    CMDLength : BYTE;
    CMD_Return : UINT;
    CMDLength_Return : BYTE;
END_VAR
VAR_INPUT
    Execute : BOOL;
END_VAR
VAR_OUTPUT
    Done : BOOL;
    Busy : BOOL;
    CommandBuffed : BOOL;
    Active : BOOL;
    Error : BOOL;
    ErrorID : UINT;
    AbortedSequence : UINT;
END_VAR
VAR_EXTERNAL
    PLC_CMDHeader : ARRAY[0..9] OF BYTE;
    EIP_OUT : ARRAY[0..255] OF BYTE;
    PLC_Header : ARRAY[0..5] OF BYTE;
    RobotCMDState : BYTE;
    Robot_CMDHeader : ARRAY[0..9] OF BYTE;
    M305 : BOOL;
END_VAR
VAR
    _e1 : R_TRIG;
END_VAR
(* ladder, written here as Structured Text *)

(* Rung 0 *)
IF Execute THEN
    CMD := UINT#16#1002;
    CMDLength := 0;
END_IF;
(* Rung 1: #PLC to Robot# / CMD Header *)
IF Execute THEN
    ToAryByte(In := CMD, Order := _LOW_HIGH, AryOut := PLC_CMDHeader[0]);
    EIP_OUT[6] := PLC_CMDHeader[0];
    EIP_OUT[7] := PLC_CMDHeader[1];
    PLC_CMDHeader[2] := CMDLength;
    EIP_OUT[8] := PLC_CMDHeader[2];
END_IF;
(* Rung 2: #Robot to PLC# / CMD Header *)
_e1(CLK := Execute AND (RobotCMDState = BYTE#0));
Busy := _e1.Q;
Done := Execute AND (RobotCMDState = BYTE#0);
M305 := Execute AND (RobotCMDState = BYTE#0);
IF Execute THEN
    AryByteTo(In := Robot_CMDHeader[0], Size := UINT#2, Order := _LOW_HIGH, OutVal := CMD_Return);
    CMDLength_Return := Robot_CMDHeader[2];
END_IF;
END_FUNCTION_BLOCK

FUNCTION_BLOCK RC_ReadActualPosition
VAR
    CMD : UINT;
    CMDLength : BYTE;
    CMD_Return : UINT;
    CMDLength_Return : BYTE;
    RobotConfig : BYTE;
    ToolNoReturn : BYTE;
    FrameNoReturn : BYTE;
END_VAR
VAR_INPUT
    Execute : BOOL;
    ToolNO : BYTE;
    FrameNo : BYTE;
END_VAR
VAR_OUTPUT
    Done : BOOL;
    Valid : BOOL;
    Busy : BOOL;
    CommandBuffered : BOOL;
    CommandAborted : BOOL;
    CommandInterrupt : BOOL;
    ParameterAccepted : BOOL;
    Error : BOOL;
    ErrorID : UINT;
    Position : ARRAY[0..11] OF Real;
    TurnNumber : ARRAY[0..3] OF BYTE;
END_VAR
VAR_EXTERNAL
    PLC_CMDHeader : ARRAY[0..9] OF BYTE;
    EIP_OUT : ARRAY[0..255] OF BYTE;
    PLC_Header : ARRAY[0..5] OF BYTE;
    PLC_CMDPayload : ARRAY[0..238] OF BYTE;
    RobotCMDState : BYTE;
    Robot_CMDPayload : ARRAY[0..119] OF BYTE;
    Robot_CMDHeader : ARRAY[0..9] OF BYTE;
    R855 : REAL;
    R857 : REAL;
    R859 : REAL;
    R861 : REAL;
    R863 : REAL;
    R865 : REAL;
    R867 : REAL;
    R869 : REAL;
    R871 : REAL;
    R873 : REAL;
    R875 : REAL;
    R877 : REAL;
    R879L : BYTE;
    R879H : BYTE;
    R880L : BYTE;
    R880H : BYTE;
    R881L : BYTE;
    R881H : BYTE;
    R882L : BYTE;
END_VAR
(* ladder, written here as Structured Text *)

(* Rung 0 *)
IF Execute THEN
    CMD := UINT#16#1003;
    CMDLength := 2;
END_IF;
(* Rung 1: #PLC to Robot# / CMD Header *)
IF Execute THEN
    ToAryByte(In := CMD, Order := _LOW_HIGH, AryOut := PLC_CMDHeader[0]);
    EIP_OUT[6] := PLC_CMDHeader[0];
    EIP_OUT[7] := PLC_CMDHeader[1];
    PLC_CMDHeader[2] := CMDLength;
    EIP_OUT[8] := PLC_CMDHeader[2];
END_IF;
(* Rung 2: #PLC to Robot# / CMD PayLoad *)
IF Execute THEN
    PLC_CMDPayload[0] := ToolNO;
    EIP_OUT[16] := PLC_CMDPayload[0];
    PLC_CMDPayload[1] := FrameNo;
    EIP_OUT[17] := PLC_CMDPayload[1];
END_IF;
(* Rung 3: #Robot to PLC# / CMD Header *)
Busy := Execute AND (RobotCMDState = BYTE#1);
(* Rung 4 *)
Done := Execute AND (RobotCMDState = BYTE#0);
IF Execute THEN
    AryByteTo(In := Robot_CMDHeader[0], Size := UINT#2, Order := _LOW_HIGH, OutVal := CMD_Return);
    CMDLength_Return := Robot_CMDHeader[2];
END_IF;

(* Rung 5: #Robot to PLC# / CMD PayLoad *)
IF Execute THEN
    AryByteTo(In := Robot_CMDPayload[0], Size := UINT#4, Order := _LOW_HIGH, OutVal := Position[0]);
    R855 := Position[0];
    AryByteTo(In := Robot_CMDPayload[4], Size := UINT#4, Order := _LOW_HIGH, OutVal := Position[1]);
    R857 := Position[1];
    AryByteTo(In := Robot_CMDPayload[8], Size := UINT#4, Order := _LOW_HIGH, OutVal := Position[2]);
    R859 := Position[2];
    AryByteTo(In := Robot_CMDPayload[12], Size := UINT#4, Order := _LOW_HIGH, OutVal := Position[3]);
    R861 := Position[3];
    AryByteTo(In := Robot_CMDPayload[16], Size := UINT#4, Order := _LOW_HIGH, OutVal := Position[4]);
    R863 := Position[4];
    AryByteTo(In := Robot_CMDPayload[20], Size := UINT#4, Order := _LOW_HIGH, OutVal := Position[5]);
    R865 := Position[5];
    AryByteTo(In := Robot_CMDPayload[24], Size := UINT#4, Order := _LOW_HIGH, OutVal := Position[6]);
    R867 := Position[6];
    AryByteTo(In := Robot_CMDPayload[28], Size := UINT#4, Order := _LOW_HIGH, OutVal := Position[7]);
    R869 := Position[7];
    AryByteTo(In := Robot_CMDPayload[32], Size := UINT#4, Order := _LOW_HIGH, OutVal := Position[8]);
    R871 := Position[8];
    AryByteTo(In := Robot_CMDPayload[36], Size := UINT#4, Order := _LOW_HIGH, OutVal := Position[9]);
    R873 := Position[9];
    AryByteTo(In := Robot_CMDPayload[40], Size := UINT#4, Order := _LOW_HIGH, OutVal := Position[10]);
    R875 := Position[10];
    AryByteTo(In := Robot_CMDPayload[44], Size := UINT#4, Order := _LOW_HIGH, OutVal := Position[11]);
    R877 := Position[11];
    TurnNumber[0] := Robot_CMDPayload[48];
    TurnNumber[1] := Robot_CMDPayload[49];
    R879L := TurnNumber[0];
    R879H := TurnNumber[1];
    TurnNumber[2] := Robot_CMDPayload[50];
    TurnNumber[3] := Robot_CMDPayload[51];
    R880L := TurnNumber[2];
    R880H := TurnNumber[3];
    RobotConfig := Robot_CMDPayload[52];
    R881L := RobotConfig;
    ToolNoReturn := Robot_CMDPayload[53];
    R881H := ToolNoReturn;
    FrameNoReturn := Robot_CMDPayload[54];
    R882L := FrameNoReturn;
END_IF;
END_FUNCTION_BLOCK

FUNCTION_BLOCK RC_ChangeSpeedOverride
VAR
    CMD : UINT;
    CMDLength : BYTE;
    CMD_Return : UINT;
    CMDLength_Return : BYTE;
END_VAR
VAR_INPUT
    Execute : BOOL;
    Over_ride : UINT;
END_VAR
VAR_OUTPUT
    Done : BOOL;
    Busy : BOOL;
    CommandBuffered : BOOL;
    Error : BOOL;
    ErrorID : UINT;
END_VAR
VAR_EXTERNAL
    PLC_CMDHeader : ARRAY[0..9] OF BYTE;
    EIP_OUT : ARRAY[0..255] OF BYTE;
    PLC_Header : ARRAY[0..5] OF BYTE;
    RobotCMDState : BYTE;
    PLC_CMDPayload : ARRAY[0..238] OF BYTE;
    Robot_CMDHeader : ARRAY[0..9] OF BYTE;
END_VAR
VAR
    _e1 : R_TRIG;
END_VAR
(* ladder, written here as Structured Text *)

(* Rung 0 *)
IF Execute THEN
    CMD := UINT#16#1004;
    CMDLength := 2;
END_IF;
(* Rung 1: #PLC to Robot# / CMD Header *)
IF Execute THEN
    ToAryByte(In := CMD, Order := _LOW_HIGH, AryOut := PLC_CMDHeader[0]);
    EIP_OUT[6] := PLC_CMDHeader[0];
    EIP_OUT[7] := PLC_CMDHeader[1];
    PLC_CMDHeader[2] := CMDLength;
    EIP_OUT[8] := PLC_CMDHeader[2];
END_IF;
(* Rung 2: #PLC to Robot# / CMD PayLoad *)
IF Execute THEN
    ToAryByte(In := Over_ride, Order := _LOW_HIGH, AryOut := PLC_CMDPayload[0]);
    EIP_OUT[16] := PLC_CMDPayload[0];
    EIP_OUT[17] := PLC_CMDPayload[1];
END_IF;
(* Rung 3: #Robot to PLC# / CMD Header *)
_e1(CLK := Execute AND (RobotCMDState = BYTE#0));
Busy := _e1.Q;
Done := Execute AND (RobotCMDState = BYTE#0);
IF Execute THEN
    AryByteTo(In := Robot_CMDHeader[0], Size := UINT#2, Order := _LOW_HIGH, OutVal := CMD_Return);
    CMDLength_Return := Robot_CMDHeader[2];
END_IF;
END_FUNCTION_BLOCK

FUNCTION_BLOCK RC_GroupContinue
VAR
    CMD : UINT;
    CMDLength : BYTE;
    CMD_Return : UINT;
    CMDLength_Return : BYTE;
END_VAR
VAR_INPUT
    Execute : BOOL;
END_VAR
VAR_OUTPUT
    Done : BOOL;
    Busy : BOOL;
    CommandBuffered : BOOL;
    Error : BOOL;
    ErrorID : UINT;
END_VAR
VAR_EXTERNAL
    PLC_CMDHeader : ARRAY[0..9] OF BYTE;
    EIP_OUT : ARRAY[0..255] OF BYTE;
    PLC_Header : ARRAY[0..5] OF BYTE;
    RobotCMDState : BYTE;
    Robot_CMDHeader : ARRAY[0..9] OF BYTE;
END_VAR
VAR
    _e1 : R_TRIG;
END_VAR
(* ladder, written here as Structured Text *)

(* Rung 0 *)
IF Execute THEN
    CMD := UINT#16#1005;
    CMDLength := 0;
END_IF;
(* Rung 1: #PLC to Robot# / CMD Header *)
IF Execute THEN
    ToAryByte(In := CMD, Order := _LOW_HIGH, AryOut := PLC_CMDHeader[0]);
    EIP_OUT[6] := PLC_CMDHeader[0];
    EIP_OUT[7] := PLC_CMDHeader[1];
    PLC_CMDHeader[2] := CMDLength;
    EIP_OUT[8] := PLC_CMDHeader[2];
END_IF;
(* Rung 2: #Robot to PLC# / CMD Header *)
_e1(CLK := Execute AND (RobotCMDState = BYTE#0));
Busy := _e1.Q;
Done := Execute AND (RobotCMDState = BYTE#0);
IF Execute THEN
    AryByteTo(In := Robot_CMDHeader[0], Size := UINT#2, Order := _LOW_HIGH, OutVal := CMD_Return);
    CMDLength_Return := Robot_CMDHeader[2];
END_IF;
END_FUNCTION_BLOCK

FUNCTION_BLOCK RC_GroupInterrupt
VAR
    CMD : UINT;
    CMDLength : BYTE;
    CMD_Return : UINT;
    CMDLength_Return : BYTE;
END_VAR
VAR_INPUT
    Execute : BOOL;
END_VAR
VAR_OUTPUT
    Done : BOOL;
    Busy : BOOL;
    CommandBuffered : BOOL;
    Active : BOOL;
    Error : BOOL;
    ErrorID : UINT;
END_VAR
VAR_EXTERNAL
    PLC_CMDHeader : ARRAY[0..9] OF BYTE;
    EIP_OUT : ARRAY[0..255] OF BYTE;
    RobotCMDState : BYTE;
    Robot_CMDHeader : ARRAY[0..9] OF BYTE;
END_VAR
VAR
    _e1 : R_TRIG;
END_VAR
(* ladder, written here as Structured Text *)

(* Rung 0 *)
IF Execute THEN
    CMD := UINT#16#1006;
    CMDLength := 0;
END_IF;
(* Rung 1: #PLC to Robot# / CMD Header *)
IF Execute THEN
    ToAryByte(In := CMD, Order := _LOW_HIGH, AryOut := PLC_CMDHeader[0]);
    EIP_OUT[6] := PLC_CMDHeader[0];
    EIP_OUT[7] := PLC_CMDHeader[1];
    PLC_CMDHeader[2] := CMDLength;
    EIP_OUT[8] := PLC_CMDHeader[2];
END_IF;
(* Rung 2: #Robot to PLC# / CMD Header *)
_e1(CLK := Execute AND (RobotCMDState = BYTE#0));
Busy := _e1.Q;
Done := Execute AND (RobotCMDState = BYTE#0);
IF Execute THEN
    AryByteTo(In := Robot_CMDHeader[0], Size := UINT#2, Order := _LOW_HIGH, OutVal := CMD_Return);
    CMDLength_Return := Robot_CMDHeader[2];
END_IF;
END_FUNCTION_BLOCK

FUNCTION_BLOCK RC_CartesionFromJoint
VAR
    CMD : UINT;
    CMDLength : BYTE;
    J1 : REAL;
    J2 : REAL;
    J3 : REAL;
    J4 : REAL;
    J5 : REAL;
    J6 : REAL;
    X_Return : REAL;
    Y_Return : REAL;
    Z_Return : REAL;
    RX_Return : REAL;
    RY_Return : REAL;
    RZ_Return : REAL;
    CMD_Return : UINT;
    CMDLength_Return : BYTE;
END_VAR
VAR_INPUT
    Execute : BOOL;
    Joint_Posion : ARRAY[0..5] OF REAL;
    Def_cartacc : REAL;
END_VAR
VAR_OUTPUT
    Done : BOOL;
    Busy : BOOL;
    CommandBuffered : BOOL;
    Error : BOOL;
    ErrorID : UINT;
END_VAR
VAR_EXTERNAL
    PLC_CMDHeader : ARRAY[0..9] OF BYTE;
    EIP_OUT : ARRAY[0..255] OF BYTE;
    PLC_CMDPayload : ARRAY[0..238] OF BYTE;
    RobotCMDState : BYTE;
    Robot_CMDPayload : ARRAY[0..119] OF BYTE;
    Robot_CMDHeader : ARRAY[0..9] OF BYTE;
    JointIN : ARRAY[0..5] OF REAL;
    CartestionReturn : ARRAY[0..5] OF REAL;
END_VAR
VAR
    _e1 : R_TRIG;
END_VAR
(* ladder, written here as Structured Text *)

(* Rung 0 *)
IF Execute THEN
    CMD := UINT#16#1007;
    CMDLength := 24;
END_IF;
(* Rung 1: #PLC to Robot# / CMD Header *)
IF Execute THEN
    ToAryByte(In := CMD, Order := _LOW_HIGH, AryOut := PLC_CMDHeader[0]);
    EIP_OUT[6] := PLC_CMDHeader[0];
    EIP_OUT[7] := PLC_CMDHeader[1];
    PLC_CMDHeader[2] := CMDLength;
    EIP_OUT[8] := PLC_CMDHeader[2];
END_IF;
(* Rung 2: #PLC to Robot# / CMD PayLoad *)
IF Execute THEN
    ToAryByte(In := Joint_Posion[0], Order := _LOW_HIGH, AryOut := PLC_CMDPayload[0]);
    AryMove(In := PLC_CMDPayload[0], AryOut := EIP_OUT[16], Size := UINT#4);
    ToAryByte(In := Joint_Posion[1], Order := _LOW_HIGH, AryOut := PLC_CMDPayload[4]);
    AryMove(In := PLC_CMDPayload[4], AryOut := EIP_OUT[20], Size := UINT#4);
    ToAryByte(In := Joint_Posion[2], Order := _LOW_HIGH, AryOut := PLC_CMDPayload[8]);
    AryMove(In := PLC_CMDPayload[8], AryOut := EIP_OUT[24], Size := UINT#4);
    ToAryByte(In := Joint_Posion[3], Order := _LOW_HIGH, AryOut := PLC_CMDPayload[12]);
    AryMove(In := PLC_CMDPayload[12], AryOut := EIP_OUT[28], Size := UINT#4);
    ToAryByte(In := Joint_Posion[4], Order := _LOW_HIGH, AryOut := PLC_CMDPayload[16]);
    AryMove(In := PLC_CMDPayload[16], AryOut := EIP_OUT[32], Size := UINT#4);
    ToAryByte(In := Joint_Posion[5], Order := _LOW_HIGH, AryOut := PLC_CMDPayload[20]);
    AryMove(In := PLC_CMDPayload[20], AryOut := EIP_OUT[36], Size := UINT#4);
END_IF;

(* Rung 3: #Robot to PLC# / CMD Header *)
_e1(CLK := Execute AND (RobotCMDState = BYTE#0));
Busy := _e1.Q;
Done := Execute AND (RobotCMDState = BYTE#0);
IF Execute THEN
    AryByteTo(In := Robot_CMDHeader[0], Size := UINT#2, Order := _LOW_HIGH, OutVal := CMD_Return);
    CMDLength_Return := Robot_CMDHeader[2];
END_IF;
(* Rung 4: #Robot to PLC# / CMD PayLoad *)
IF Execute THEN
    AryByteTo(In := Robot_CMDPayload[0], Size := UINT#4, Order := _LOW_HIGH, OutVal := CartestionReturn[0]);
    AryByteTo(In := Robot_CMDPayload[4], Size := UINT#4, Order := _LOW_HIGH, OutVal := CartestionReturn[1]);
    AryByteTo(In := Robot_CMDPayload[8], Size := UINT#4, Order := _LOW_HIGH, OutVal := CartestionReturn[2]);
    AryByteTo(In := Robot_CMDPayload[12], Size := UINT#4, Order := _LOW_HIGH, OutVal := CartestionReturn[3]);
    AryByteTo(In := Robot_CMDPayload[16], Size := UINT#4, Order := _LOW_HIGH, OutVal := CartestionReturn[4]);
    AryByteTo(In := Robot_CMDPayload[20], Size := UINT#4, Order := _LOW_HIGH, OutVal := CartestionReturn[5]);
END_IF;
END_FUNCTION_BLOCK

FUNCTION_BLOCK RC_JointFromCartesion
VAR
    CMD : UINT;
    CMDLength : BYTE;
    X : REAL;
    Y : REAL;
    Z : REAL;
    RX : REAL;
    RY : REAL;
    RZ : REAL;
    J1_Return : REAL;
    J2_Return : REAL;
    J3_Return : REAL;
    J4_Return : REAL;
    J5_Return : REAL;
    J6_Return : REAL;
    CMD_Return : UINT;
    CMDLength_Return : BYTE;
END_VAR
VAR_INPUT
    Execute : BOOL;
    Cartesion_Posion : ARRAY[0..5] OF REAL;
    Config : DINT;
    Flag : BYTE;
END_VAR
VAR_OUTPUT
    Done : BOOL;
    Busy : BOOL;
    CommandBuffered : BOOL;
    Error : BOOL;
    ErrorID : UINT;
END_VAR
VAR_EXTERNAL
    PLC_CMDHeader : ARRAY[0..9] OF BYTE;
    EIP_OUT : ARRAY[0..255] OF BYTE;
    PLC_CMDPayload : ARRAY[0..238] OF BYTE;
    RobotCMDState : BYTE;
    Robot_CMDPayload : ARRAY[0..119] OF BYTE;
    Robot_CMDHeader : ARRAY[0..9] OF BYTE;
    JointReturn : ARRAY[0..5] OF REAL;
END_VAR
VAR
    _e1 : R_TRIG;
END_VAR
(* ladder, written here as Structured Text *)

(* Rung 0 *)
IF Execute THEN
    CMD := UINT#16#1008;
    CMDLength := 29;
END_IF;
(* Rung 1: #PLC to Robot# / CMD Header *)
IF Execute THEN
    ToAryByte(In := CMD, Order := _LOW_HIGH, AryOut := PLC_CMDHeader[0]);
    EIP_OUT[6] := PLC_CMDHeader[0];
    EIP_OUT[7] := PLC_CMDHeader[1];
    PLC_CMDHeader[2] := CMDLength;
    EIP_OUT[8] := PLC_CMDHeader[2];
END_IF;
(* Rung 2: #PLC to Robot# / CMD PayLoad *)
IF Execute THEN
    ToAryByte(In := Cartesion_Posion[0], Order := _LOW_HIGH, AryOut := PLC_CMDPayload[0]);
    AryMove(In := PLC_CMDPayload[0], AryOut := EIP_OUT[16], Size := UINT#4);
    ToAryByte(In := Cartesion_Posion[1], Order := _LOW_HIGH, AryOut := PLC_CMDPayload[4]);
    AryMove(In := PLC_CMDPayload[4], AryOut := EIP_OUT[20], Size := UINT#4);
    ToAryByte(In := Cartesion_Posion[2], Order := _LOW_HIGH, AryOut := PLC_CMDPayload[8]);
    AryMove(In := PLC_CMDPayload[8], AryOut := EIP_OUT[24], Size := UINT#4);
    ToAryByte(In := Cartesion_Posion[3], Order := _LOW_HIGH, AryOut := PLC_CMDPayload[12]);
    AryMove(In := PLC_CMDPayload[12], AryOut := EIP_OUT[28], Size := UINT#4);
    ToAryByte(In := Cartesion_Posion[4], Order := _LOW_HIGH, AryOut := PLC_CMDPayload[16]);
    AryMove(In := PLC_CMDPayload[16], AryOut := EIP_OUT[32], Size := UINT#4);
    ToAryByte(In := Cartesion_Posion[5], Order := _LOW_HIGH, AryOut := PLC_CMDPayload[20]);
    AryMove(In := PLC_CMDPayload[20], AryOut := EIP_OUT[36], Size := UINT#4);
    ToAryByte(In := Config, Order := _LOW_HIGH, AryOut := PLC_CMDPayload[24]);
    AryMove(In := PLC_CMDPayload[24], AryOut := EIP_OUT[40], Size := UINT#4);
    PLC_CMDPayload[28] := Flag;
    EIP_OUT[44] := PLC_CMDPayload[28];
END_IF;

(* Rung 3: #Robot to PLC# / CMD Header *)
_e1(CLK := Execute AND (RobotCMDState = BYTE#0));
Busy := _e1.Q;
Done := Execute AND (RobotCMDState = BYTE#0);
IF Execute THEN
    AryByteTo(In := Robot_CMDHeader[0], Size := UINT#2, Order := _LOW_HIGH, OutVal := CMD_Return);
    CMDLength_Return := Robot_CMDHeader[2];
END_IF;
(* Rung 4: #Robot to PLC# / CMD PayLoad *)
IF Execute THEN
    AryByteTo(In := Robot_CMDPayload[0], Size := UINT#4, Order := _LOW_HIGH, OutVal := JointReturn[0]);
    AryByteTo(In := Robot_CMDPayload[4], Size := UINT#4, Order := _LOW_HIGH, OutVal := JointReturn[1]);
    AryByteTo(In := Robot_CMDPayload[8], Size := UINT#4, Order := _LOW_HIGH, OutVal := JointReturn[2]);
    AryByteTo(In := Robot_CMDPayload[12], Size := UINT#4, Order := _LOW_HIGH, OutVal := JointReturn[3]);
    AryByteTo(In := Robot_CMDPayload[16], Size := UINT#4, Order := _LOW_HIGH, OutVal := JointReturn[4]);
    AryByteTo(In := Robot_CMDPayload[20], Size := UINT#4, Order := _LOW_HIGH, OutVal := JointReturn[5]);
END_IF;
END_FUNCTION_BLOCK

FUNCTION_BLOCK RC_WriteFrameData
VAR
    CMD : UINT;
    CMDLength : BYTE;
    CMDPayLoad : STRING[256];
    ReferenceFrame : BYTE;
    CMD_Return : UINT;
    CMDLength_Return : BYTE;
END_VAR
VAR_INPUT
    Execute : BOOL;
    FrameNo : BYTE;
    FrameData : ARRAY[0..5] OF REAL;
END_VAR
VAR_OUTPUT
    Done : BOOL;
    Busy : BOOL;
    CommandBuffered : BOOL;
    CommandAborted : BOOL;
    CommandInterrupt : BOOL;
    Error : BOOL;
    ErrorID : UINT;
END_VAR
VAR_INPUT
    X : REAL;
    Y : REAL;
    Z : REAL;
    RX : REAL;
    RY : REAL;
    RZ : REAL;
END_VAR
VAR_EXTERNAL
    PLC_CMDHeader : ARRAY[0..9] OF BYTE;
    EIP_OUT : ARRAY[0..255] OF BYTE;
    PLC_CMDPayload : ARRAY[0..238] OF BYTE;
    RobotCMDState : BYTE;
    Robot_CMDPayload : ARRAY[0..119] OF BYTE;
    Robot_CMDHeader : ARRAY[0..9] OF BYTE;
END_VAR
VAR
    _e1 : R_TRIG;
END_VAR
(* ladder, written here as Structured Text *)

(* Rung 0 *)
IF Execute THEN
    CMD := UINT#16#2002;
    CMDLength := 26;
END_IF;
(* Rung 1: #PLC to Robot# / CMD Header *)
IF Execute THEN
    ToAryByte(In := CMD, Order := _LOW_HIGH, AryOut := PLC_CMDHeader[0]);
    EIP_OUT[6] := PLC_CMDHeader[0];
    EIP_OUT[7] := PLC_CMDHeader[1];
    PLC_CMDHeader[2] := CMDLength;
    EIP_OUT[8] := PLC_CMDHeader[2];
    ToAryByte(In := CMDPayLoad, Order := _LOW_HIGH, AryOut := PLC_CMDPayload[0]);
    EIP_OUT[16] := PLC_CMDPayload[0];
    EIP_OUT[17] := PLC_CMDPayload[1];
END_IF;

(* Rung 2: #PLC to Robot# / CMD PayLoad *)
IF Execute THEN
    ToAryByte(In := X, Order := _LOW_HIGH, AryOut := Robot_CMDPayload[0]);
    AryMove(In := Robot_CMDPayload[0], AryOut := EIP_OUT[16], Size := UINT#4);
    ToAryByte(In := Y, Order := _LOW_HIGH, AryOut := Robot_CMDPayload[4]);
    AryMove(In := Robot_CMDPayload[4], AryOut := EIP_OUT[20], Size := UINT#4);
    ToAryByte(In := Z, Order := _LOW_HIGH, AryOut := Robot_CMDPayload[8]);
    AryMove(In := Robot_CMDPayload[8], AryOut := EIP_OUT[24], Size := UINT#4);
    ToAryByte(In := RX, Order := _LOW_HIGH, AryOut := Robot_CMDPayload[12]);
    AryMove(In := Robot_CMDPayload[12], AryOut := EIP_OUT[28], Size := UINT#4);
    ToAryByte(In := RY, Order := _LOW_HIGH, AryOut := Robot_CMDPayload[16]);
    AryMove(In := Robot_CMDPayload[16], AryOut := EIP_OUT[32], Size := UINT#4);
    ToAryByte(In := RZ, Order := _LOW_HIGH, AryOut := Robot_CMDPayload[20]);
    AryMove(In := Robot_CMDPayload[20], AryOut := EIP_OUT[36], Size := UINT#4);
    Robot_CMDPayload[24] := FrameNo;
    EIP_OUT[40] := Robot_CMDPayload[24];
    Robot_CMDPayload[25] := ReferenceFrame;
    EIP_OUT[41] := Robot_CMDPayload[25];
END_IF;
(* Rung 3: #Robot to PLC# / CMD Header *)
_e1(CLK := Execute AND (RobotCMDState = BYTE#0));
Busy := _e1.Q;
Done := Execute AND (RobotCMDState = BYTE#0);
IF Execute THEN
    AryByteTo(In := Robot_CMDHeader[0], Size := UINT#2, Order := _LOW_HIGH, OutVal := CMD_Return);
    CMDLength_Return := Robot_CMDHeader[2];
END_IF;
END_FUNCTION_BLOCK

FUNCTION_BLOCK RC_ReadFrameData
VAR
    CMD : UINT;
    CMDLength : BYTE;
    CMD_Return : UINT;
    CMDLength_Return : BYTE;
END_VAR
VAR_INPUT
    Execute : BOOL;
    FrameNo : BYTE;
END_VAR
VAR_OUTPUT
    Done : BOOL;
    Busy : BOOL;
    CommandBuffered : BOOL;
    Error : BOOL;
    ErrorID : UINT;
    FrameNoReturn : BYTE;
    ToolData : STRING[256];
    X : REAL;
    Y : REAL;
    Z : REAL;
    RX : REAL;
    RY : REAL;
    RZ : REAL;
END_VAR
VAR_EXTERNAL
    PLC_CMDHeader : ARRAY[0..9] OF BYTE;
    EIP_OUT : ARRAY[0..255] OF BYTE;
    RobotCMDState : BYTE;
    PLC_CMDPayload : ARRAY[0..238] OF BYTE;
    EIP_IN : ARRAY[0..255] OF BYTE;
    Robot_CMDPayload : ARRAY[0..119] OF BYTE;
    Robot_CMDHeader : ARRAY[0..9] OF BYTE;
END_VAR
VAR
    _e1 : R_TRIG;
END_VAR
(* ladder, written here as Structured Text *)

(* Rung 0 *)
IF Execute THEN
    CMD := UINT#16#2003;
    CMDLength := 1;
END_IF;
(* Rung 1: #PLC to Robot# / CMD Header *)
IF Execute THEN
    ToAryByte(In := CMD, Order := _LOW_HIGH, AryOut := PLC_CMDHeader[0]);
    EIP_OUT[6] := PLC_CMDHeader[0];
    EIP_OUT[7] := PLC_CMDHeader[1];
    PLC_CMDHeader[2] := CMDLength;
    EIP_OUT[8] := PLC_CMDHeader[2];
END_IF;
(* Rung 2: #PLC to Robot# / CMD PayLoad *)
IF Execute THEN
    ToAryByte(In := FrameNo, Order := _LOW_HIGH, AryOut := PLC_CMDPayload[0]);
    EIP_OUT[16] := PLC_CMDPayload[0];
END_IF;
(* Rung 3: #Robot to PLC# / CMD Header *)
_e1(CLK := Execute AND (RobotCMDState = BYTE#0));
Busy := _e1.Q;
Done := Execute AND (RobotCMDState = BYTE#0);
IF Execute THEN
    AryByteTo(In := Robot_CMDHeader[0], Size := UINT#2, Order := _LOW_HIGH, OutVal := CMD_Return);
    CMDLength_Return := Robot_CMDHeader[2];
END_IF;
(* Rung 4: #Robot to PLC# / CMD PayLoad *)
IF Execute THEN
    AryByteTo(In := Robot_CMDPayload[0], Size := UINT#4, Order := _LOW_HIGH, OutVal := X);
    AryByteTo(In := Robot_CMDPayload[4], Size := UINT#4, Order := _LOW_HIGH, OutVal := Y);
    AryByteTo(In := Robot_CMDPayload[8], Size := UINT#4, Order := _LOW_HIGH, OutVal := Z);
    AryByteTo(In := Robot_CMDPayload[12], Size := UINT#4, Order := _LOW_HIGH, OutVal := RX);
    AryByteTo(In := Robot_CMDPayload[16], Size := UINT#4, Order := _LOW_HIGH, OutVal := RY);
    AryByteTo(In := Robot_CMDPayload[20], Size := UINT#4, Order := _LOW_HIGH, OutVal := RZ);
    FrameNoReturn := Robot_CMDPayload[24];
END_IF;
END_FUNCTION_BLOCK

FUNCTION_BLOCK RC_WriteLoadData
VAR
    CMD : UINT;
    CMDLength : BYTE;
    CMD_Return : UINT;
    CMDLength_Return : BYTE;
END_VAR
VAR_INPUT
    Execute : BOOL;
    LoadNo : BYTE;
    LoadData : ARRAY[0..3] OF REAL;
END_VAR
VAR_OUTPUT
    Done : BOOL;
    Busy : BOOL;
    CommandBuffered : BOOL;
    CommandAborted : BOOL;
    CommandInterrupt : BOOL;
    Error : BOOL;
    ErrorID : UINT;
END_VAR
VAR_INPUT
    mass : REAL;
    X_IN : REAL;
    Y_IN : REAL;
    Z_IN : REAL;
END_VAR
VAR_EXTERNAL
    PLC_CMDHeader : ARRAY[0..9] OF BYTE;
    EIP_OUT : ARRAY[0..255] OF BYTE;
    PLC_CMDPayload : ARRAY[0..238] OF BYTE;
    RobotCMDState : BYTE;
    Robot_CMDHeader : ARRAY[0..9] OF BYTE;
END_VAR
VAR
    _e1 : R_TRIG;
END_VAR
(* ladder, written here as Structured Text *)

(* Rung 0 *)
IF Execute THEN
    CMD := UINT#16#2004;
    CMDLength := 17;
END_IF;
(* Rung 1: #PLC to Robot# / CMD Header *)
IF Execute THEN
    ToAryByte(In := CMD, Order := _LOW_HIGH, AryOut := PLC_CMDHeader[0]);
    EIP_OUT[6] := PLC_CMDHeader[0];
    EIP_OUT[7] := PLC_CMDHeader[1];
    PLC_CMDHeader[2] := CMDLength;
    EIP_OUT[8] := PLC_CMDHeader[2];
END_IF;
(* Rung 2: #PLC to Robot# / CMD PayLoad *)
IF Execute THEN
    ToAryByte(In := mass, Order := _LOW_HIGH, AryOut := PLC_CMDPayload[0]);
    AryMove(In := PLC_CMDPayload[0], AryOut := EIP_OUT[16], Size := UINT#4);
    ToAryByte(In := X_IN, Order := _LOW_HIGH, AryOut := PLC_CMDPayload[4]);
    AryMove(In := PLC_CMDPayload[4], AryOut := EIP_OUT[20], Size := UINT#4);
    ToAryByte(In := Y_IN, Order := _LOW_HIGH, AryOut := PLC_CMDPayload[8]);
    AryMove(In := PLC_CMDPayload[8], AryOut := EIP_OUT[24], Size := UINT#4);
    ToAryByte(In := Z_IN, Order := _LOW_HIGH, AryOut := PLC_CMDPayload[12]);
    AryMove(In := PLC_CMDPayload[12], AryOut := EIP_OUT[28], Size := UINT#4);
    ToAryByte(In := LoadNo, Order := _LOW_HIGH, AryOut := PLC_CMDPayload[16]);
    EIP_OUT[32] := PLC_CMDPayload[16];
END_IF;
(* Rung 3: #Robot to PLC# / CMD Header *)
_e1(CLK := Execute AND (RobotCMDState = BYTE#0));
Busy := _e1.Q;
Done := Execute AND (RobotCMDState = BYTE#0);
IF Execute THEN
    AryByteTo(In := Robot_CMDHeader[0], Size := UINT#2, Order := _LOW_HIGH, OutVal := CMD_Return);
    CMDLength_Return := Robot_CMDHeader[2];
END_IF;
END_FUNCTION_BLOCK

FUNCTION_BLOCK RC_ReadLoadData
VAR
    CMD : UINT;
    CMDLength : BYTE;
    CMD_Return : UINT;
    CMDLength_Return : BYTE;
END_VAR
VAR_INPUT
    Execute : BOOL;
    LoadNo : BYTE;
END_VAR
VAR_OUTPUT
    Done : BOOL;
    Busy : BOOL;
    CommandBuffered : BOOL;
    Error : BOOL;
    ErrorID : UINT;
    LoadNoReturn : BYTE;
    LoadData : BYTE;
    mass_Return : REAL;
    X_Return : REAL;
    Y_Return : REAL;
    Z_Return : REAL;
END_VAR
VAR_EXTERNAL
    PLC_CMDHeader : ARRAY[0..9] OF BYTE;
    EIP_OUT : ARRAY[0..255] OF BYTE;
    PLC_CMDPayload : ARRAY[0..238] OF BYTE;
    RobotCMDState : BYTE;
    Robot_CMDPayload : ARRAY[0..119] OF BYTE;
    EIP_IN : ARRAY[0..255] OF BYTE;
    Robot_CMDHeader : ARRAY[0..9] OF BYTE;
END_VAR
VAR
    _e1 : R_TRIG;
END_VAR
(* ladder, written here as Structured Text *)

(* Rung 0 *)
IF Execute THEN
    CMD := UINT#16#2005;
    CMDLength := 1;
END_IF;
(* Rung 1: #PLC to Robot# / CMD Header *)
IF Execute THEN
    ToAryByte(In := CMD, Order := _LOW_HIGH, AryOut := PLC_CMDHeader[0]);
    EIP_OUT[6] := PLC_CMDHeader[0];
    EIP_OUT[7] := PLC_CMDHeader[1];
    PLC_CMDHeader[2] := CMDLength;
    EIP_OUT[8] := PLC_CMDHeader[2];
END_IF;
(* Rung 2: #PLC to Robot# / CMD PayLoad *)
IF Execute THEN
    ToAryByte(In := LoadNo, Order := _LOW_HIGH, AryOut := PLC_CMDPayload[0]);
    EIP_OUT[16] := PLC_CMDPayload[0];
END_IF;
(* Rung 3: #Robot to PLC# / CMD Header *)
_e1(CLK := Execute AND (RobotCMDState = BYTE#0));
Busy := _e1.Q;
Done := Execute AND (RobotCMDState = BYTE#0);
IF Execute THEN
    AryByteTo(In := Robot_CMDHeader[0], Size := UINT#2, Order := _LOW_HIGH, OutVal := CMD_Return);
    CMDLength_Return := Robot_CMDHeader[2];
END_IF;
(* Rung 4: #Robot to PLC# / CMD PayLoad *)
IF Execute THEN
    AryByteTo(In := Robot_CMDPayload[0], Size := UINT#4, Order := _LOW_HIGH, OutVal := mass_Return);
    AryByteTo(In := Robot_CMDPayload[4], Size := UINT#4, Order := _LOW_HIGH, OutVal := X_Return);
    AryByteTo(In := Robot_CMDPayload[8], Size := UINT#4, Order := _LOW_HIGH, OutVal := Y_Return);
    AryByteTo(In := Robot_CMDPayload[12], Size := UINT#4, Order := _LOW_HIGH, OutVal := Z_Return);
    LoadNoReturn := Robot_CMDPayload[16];
END_IF;
END_FUNCTION_BLOCK

FUNCTION_BLOCK RC_WriteRobotReferenceDynamics
VAR
    CMD : UINT;
    CMDLength : BYTE;
    CMD_Return : UINT;
    CMDLength_Return : BYTE;
END_VAR
VAR_INPUT
    Execute : BOOL;
    DynamicValues : ARRAY[0..1] OF REAL;
END_VAR
VAR_OUTPUT
    Done : BOOL;
    Busy : BOOL;
    CommandBuffered : BOOL;
    Error : BOOL;
    ErrorID : UINT;
    ReferenceDynamicValues : ARRAY[0..1] OF REAL;
END_VAR
VAR_INPUT
    max_cartvel : REAL;
    max_cartacc : REAL;
END_VAR
VAR_EXTERNAL
    PLC_CMDHeader : ARRAY[0..9] OF BYTE;
    EIP_OUT : ARRAY[0..255] OF BYTE;
    PLC_CMDPayload : ARRAY[0..238] OF BYTE;
    RobotCMDState : BYTE;
    Robot_CMDHeader : ARRAY[0..9] OF BYTE;
END_VAR
VAR
    _e1 : R_TRIG;
END_VAR
(* ladder, written here as Structured Text *)

(* Rung 0 *)
IF Execute THEN
    CMD := UINT#16#2006;
    CMDLength := 8;
END_IF;
(* Rung 1: #PLC to Robot# / CMD Header *)
IF Execute THEN
    ToAryByte(In := CMD, Order := _LOW_HIGH, AryOut := PLC_CMDHeader[0]);
    EIP_OUT[6] := PLC_CMDHeader[0];
    EIP_OUT[7] := PLC_CMDHeader[1];
    PLC_CMDHeader[2] := CMDLength;
    EIP_OUT[8] := PLC_CMDHeader[2];
END_IF;
(* Rung 2: #PLC to Robot# / CMD PayLoad *)
IF Execute THEN
    ToAryByte(In := max_cartvel, Order := _LOW_HIGH, AryOut := PLC_CMDPayload[0]);
    AryMove(In := PLC_CMDPayload[0], AryOut := EIP_OUT[16], Size := UINT#4);
    ToAryByte(In := max_cartacc, Order := _LOW_HIGH, AryOut := PLC_CMDPayload[4]);
    AryMove(In := PLC_CMDPayload[4], AryOut := EIP_OUT[20], Size := UINT#4);
END_IF;
(* Rung 3: #Robot to PLC# / CMD Header *)
_e1(CLK := Execute AND (RobotCMDState = BYTE#0));
Busy := _e1.Q;
Done := Execute AND (RobotCMDState = BYTE#0);
IF Execute THEN
    AryByteTo(In := Robot_CMDHeader[0], Size := UINT#2, Order := _LOW_HIGH, OutVal := CMD_Return);
    CMDLength_Return := Robot_CMDHeader[2];
END_IF;
END_FUNCTION_BLOCK

FUNCTION_BLOCK RC_ReadRobotReferenceDynamics
VAR
    CMD : UINT;
    CMDLength : BYTE;
    CMD_Return : UINT;
    CMDLength_Return : BYTE;
END_VAR
VAR_INPUT
    Execute : BOOL;
END_VAR
VAR_OUTPUT
    Done : BOOL;
    Busy : BOOL;
    CommandBuffered : BOOL;
    Error : BOOL;
    ErrorID : UINT;
    DynamicValues : ARRAY[0..1] OF REAL;
    max_cartvelReturn : REAL;
    max_cartaccReturn : REAL;
END_VAR
VAR_EXTERNAL
    PLC_CMDHeader : ARRAY[0..9] OF BYTE;
    EIP_OUT : ARRAY[0..255] OF BYTE;
    RobotCMDState : BYTE;
    Robot_CMDPayload : ARRAY[0..119] OF BYTE;
    Robot_CMDHeader : ARRAY[0..9] OF BYTE;
END_VAR
VAR
    _e1 : R_TRIG;
END_VAR
(* ladder, written here as Structured Text *)

(* Rung 0 *)
IF Execute THEN
    CMD := UINT#16#2007;
    CMDLength := 0;
END_IF;
(* Rung 1: #PLC to Robot# / CMD Header *)
IF Execute THEN
    ToAryByte(In := CMD, Order := _LOW_HIGH, AryOut := PLC_CMDHeader[0]);
    EIP_OUT[6] := PLC_CMDHeader[0];
    EIP_OUT[7] := PLC_CMDHeader[1];
    PLC_CMDHeader[2] := CMDLength;
    EIP_OUT[8] := PLC_CMDHeader[2];
END_IF;
(* Rung 2: #Robot to PLC# / CMD Header *)
_e1(CLK := Execute AND (RobotCMDState = BYTE#0));
Busy := _e1.Q;
Done := Execute AND (RobotCMDState = BYTE#0);
IF Execute THEN
    AryByteTo(In := Robot_CMDHeader[0], Size := UINT#2, Order := _LOW_HIGH, OutVal := CMD_Return);
    CMDLength_Return := Robot_CMDHeader[2];
END_IF;
(* Rung 3: #Robot to PLC# / CMD PayLoad *)
IF Execute THEN
    AryByteTo(In := Robot_CMDPayload[0], Size := UINT#4, Order := _LOW_HIGH, OutVal := max_cartvelReturn);
    AryByteTo(In := Robot_CMDPayload[4], Size := UINT#4, Order := _LOW_HIGH, OutVal := max_cartaccReturn);
END_IF;
END_FUNCTION_BLOCK

FUNCTION_BLOCK RC_WriteRobotDefaultDynamic
VAR
    CMD : UINT;
    CMDLength : BYTE;
    CMD_Return : UINT;
    CMDLength_Return : BYTE;
END_VAR
VAR_INPUT
    Execute : BOOL;
    Def_cartval : REAL;
    Def_cartacc : REAL;
END_VAR
VAR_OUTPUT
    Done : BOOL;
    Busy : BOOL;
    CommandBuffered : BOOL;
    Error : BOOL;
    ErrorID : UINT;
END_VAR
VAR_EXTERNAL
    PLC_CMDHeader : ARRAY[0..9] OF BYTE;
    EIP_OUT : ARRAY[0..255] OF BYTE;
    RobotCMDState : BYTE;
    PLC_CMDPayload : ARRAY[0..238] OF BYTE;
    Robot_CMDHeader : ARRAY[0..9] OF BYTE;
END_VAR
VAR
    _e1 : R_TRIG;
END_VAR
(* ladder, written here as Structured Text *)

(* Rung 0 *)
IF Execute THEN
    CMD := UINT#16#2008;
    CMDLength := 8;
END_IF;
(* Rung 1: #PLC to Robot# / CMD Header *)
IF Execute THEN
    ToAryByte(In := CMD, Order := _LOW_HIGH, AryOut := PLC_CMDHeader[0]);
    EIP_OUT[6] := PLC_CMDHeader[0];
    EIP_OUT[7] := PLC_CMDHeader[1];
    PLC_CMDHeader[2] := CMDLength;
    EIP_OUT[8] := PLC_CMDHeader[2];
END_IF;
(* Rung 2: #PLC to Robot# / CMD PayLoad *)
IF Execute THEN
    ToAryByte(In := Def_cartval, Order := _LOW_HIGH, AryOut := PLC_CMDPayload[0]);
    AryMove(In := PLC_CMDPayload[0], AryOut := EIP_OUT[16], Size := UINT#4);
    ToAryByte(In := Def_cartacc, Order := _LOW_HIGH, AryOut := PLC_CMDPayload[4]);
    AryMove(In := PLC_CMDPayload[4], AryOut := EIP_OUT[20], Size := UINT#4);
END_IF;
(* Rung 3: #Robot to PLC# / CMD Header *)
_e1(CLK := Execute AND (RobotCMDState = BYTE#0));
Busy := _e1.Q;
Done := Execute AND (RobotCMDState = BYTE#0);
IF Execute THEN
    AryByteTo(In := Robot_CMDHeader[0], Size := UINT#2, Order := _LOW_HIGH, OutVal := CMD_Return);
    CMDLength_Return := Robot_CMDHeader[2];
END_IF;
END_FUNCTION_BLOCK

FUNCTION_BLOCK RC_ReadRobotDefaultDynamic
VAR
    CMD : UINT;
    CMDLength : BYTE;
    CMD_Return : UINT;
    CMDLength_Return : BYTE;
END_VAR
VAR_INPUT
    Execute : BOOL;
END_VAR
VAR_OUTPUT
    Done : BOOL;
    Busy : BOOL;
    CommandBuffered : BOOL;
    Error : BOOL;
    ErrorID : UINT;
    Def_cartvelReturn : REAL;
    Def_cartaccReturn : REAL;
END_VAR
VAR_EXTERNAL
    PLC_CMDHeader : ARRAY[0..9] OF BYTE;
    EIP_OUT : ARRAY[0..255] OF BYTE;
    RobotCMDState : BYTE;
    Robot_CMDPayload : ARRAY[0..119] OF BYTE;
    Robot_CMDHeader : ARRAY[0..9] OF BYTE;
END_VAR
VAR
    _e1 : R_TRIG;
END_VAR
(* ladder, written here as Structured Text *)

(* Rung 0 *)
IF Execute THEN
    CMD := UINT#16#2009;
    CMDLength := 0;
END_IF;
(* Rung 1: #PLC to Robot# / CMD Header *)
IF Execute THEN
    ToAryByte(In := CMD, Order := _LOW_HIGH, AryOut := PLC_CMDHeader[0]);
    EIP_OUT[6] := PLC_CMDHeader[0];
    EIP_OUT[7] := PLC_CMDHeader[1];
    PLC_CMDHeader[2] := CMDLength;
    EIP_OUT[8] := PLC_CMDHeader[2];
END_IF;
(* Rung 2: #Robot to PLC# / CMD Header *)
_e1(CLK := Execute AND (RobotCMDState = BYTE#0));
Busy := _e1.Q;
Done := Execute AND (RobotCMDState = BYTE#0);
IF Execute THEN
    AryByteTo(In := Robot_CMDHeader[0], Size := UINT#2, Order := _LOW_HIGH, OutVal := CMD_Return);
    CMDLength_Return := Robot_CMDHeader[2];
END_IF;
(* Rung 3: #Robot to PLC# / CMD PayLoad *)
IF Execute THEN
    AryByteTo(In := Robot_CMDPayload[0], Size := UINT#4, Order := _LOW_HIGH, OutVal := Def_cartvelReturn);
    AryByteTo(In := Robot_CMDPayload[4], Size := UINT#4, Order := _LOW_HIGH, OutVal := Def_cartaccReturn);
END_IF;
END_FUNCTION_BLOCK

FUNCTION_BLOCK RC_WriteRobotSwLimits
VAR
    CMD : UINT;
    CMDLength : BYTE;
    CMD_Return : UINT;
    CMDLength_Return : BYTE;
END_VAR
VAR_INPUT
    Execute : BOOL;
    LimitValues : ARRAY[0..1] OF REAL;
    ResetToFactoryDefaults : BOOL;
END_VAR
VAR_OUTPUT
    Done : BOOL;
    Busy : BOOL;
    CommandBuffered : BOOL;
    Error : BOOL;
    ErrorID : UINT;
    RestartRequested : BOOL;
END_VAR
VAR_INPUT
    J1_max : REAL;
    J2_max : REAL;
    J3_max : REAL;
    J4_max : REAL;
    J5_max : REAL;
    J6_max : REAL;
    J1_min : REAL;
    J2_min : REAL;
    J3_min : REAL;
    J4_min : REAL;
    J5_min : REAL;
    J6_min : REAL;
END_VAR
VAR_EXTERNAL
    PLC_CMDHeader : ARRAY[0..9] OF BYTE;
    EIP_OUT : ARRAY[0..255] OF BYTE;
    RobotCMDState : BYTE;
    PLC_CMDPayload : ARRAY[0..238] OF BYTE;
    Robot_CMDHeader : ARRAY[0..9] OF BYTE;
END_VAR
VAR
    _e1 : R_TRIG;
END_VAR
(* ladder, written here as Structured Text *)

(* Rung 0 *)
IF Execute THEN
    CMD := UINT#16#2010;
    CMDLength := 48;
END_IF;
(* Rung 1: #PLC to Robot# / CMD Header *)
IF Execute THEN
    ToAryByte(In := CMD, Order := _LOW_HIGH, AryOut := PLC_CMDHeader[0]);
    EIP_OUT[6] := PLC_CMDHeader[0];
    EIP_OUT[7] := PLC_CMDHeader[1];
    PLC_CMDHeader[2] := CMDLength;
    EIP_OUT[8] := PLC_CMDHeader[2];
END_IF;

(* Rung 2: #PLC to Robot# / CMD PayLoad *)
IF Execute THEN
    ToAryByte(In := J1_max, Order := _LOW_HIGH, AryOut := PLC_CMDPayload[0]);
    AryMove(In := PLC_CMDPayload[0], AryOut := EIP_OUT[16], Size := UINT#4);
    ToAryByte(In := J2_max, Order := _LOW_HIGH, AryOut := PLC_CMDPayload[4]);
    AryMove(In := PLC_CMDPayload[4], AryOut := EIP_OUT[20], Size := UINT#4);
    ToAryByte(In := J3_max, Order := _LOW_HIGH, AryOut := PLC_CMDPayload[8]);
    AryMove(In := PLC_CMDPayload[8], AryOut := EIP_OUT[24], Size := UINT#4);
    ToAryByte(In := J4_max, Order := _LOW_HIGH, AryOut := PLC_CMDPayload[12]);
    AryMove(In := PLC_CMDPayload[12], AryOut := EIP_OUT[28], Size := UINT#4);
    ToAryByte(In := J5_max, Order := _LOW_HIGH, AryOut := PLC_CMDPayload[16]);
    AryMove(In := PLC_CMDPayload[16], AryOut := EIP_OUT[32], Size := UINT#4);
    ToAryByte(In := J6_max, Order := _LOW_HIGH, AryOut := PLC_CMDPayload[20]);
    AryMove(In := PLC_CMDPayload[20], AryOut := EIP_OUT[36], Size := UINT#4);
    ToAryByte(In := J1_min, Order := _LOW_HIGH, AryOut := PLC_CMDPayload[24]);
    AryMove(In := PLC_CMDPayload[24], AryOut := EIP_OUT[40], Size := UINT#4);
    ToAryByte(In := J2_min, Order := _LOW_HIGH, AryOut := PLC_CMDPayload[28]);
    AryMove(In := PLC_CMDPayload[28], AryOut := EIP_OUT[44], Size := UINT#4);
    ToAryByte(In := J3_min, Order := _LOW_HIGH, AryOut := PLC_CMDPayload[32]);
    AryMove(In := PLC_CMDPayload[32], AryOut := EIP_OUT[48], Size := UINT#4);
    ToAryByte(In := J4_min, Order := _LOW_HIGH, AryOut := PLC_CMDPayload[36]);
    AryMove(In := PLC_CMDPayload[36], AryOut := EIP_OUT[52], Size := UINT#4);
    ToAryByte(In := J5_min, Order := _LOW_HIGH, AryOut := PLC_CMDPayload[40]);
    AryMove(In := PLC_CMDPayload[40], AryOut := EIP_OUT[56], Size := UINT#4);
    ToAryByte(In := J6_min, Order := _LOW_HIGH, AryOut := PLC_CMDPayload[44]);
    AryMove(In := PLC_CMDPayload[44], AryOut := EIP_OUT[60], Size := UINT#4);
END_IF;

(* Rung 3: #Robot to PLC# / CMD Header *)
_e1(CLK := Execute AND (RobotCMDState = BYTE#0));
Busy := _e1.Q;
Done := Execute AND (RobotCMDState = BYTE#0);
IF Execute THEN
    AryByteTo(In := Robot_CMDHeader[0], Size := UINT#2, Order := _LOW_HIGH, OutVal := CMD_Return);
    CMDLength_Return := Robot_CMDHeader[2];
END_IF;
END_FUNCTION_BLOCK

FUNCTION_BLOCK RC_ReadRobotSwLimits
VAR
    CMD : UINT;
    CMDLength : BYTE;
    CMD_Return : UINT;
    CMDLength_Return : BYTE;
END_VAR
VAR_INPUT
    Execute : BOOL;
END_VAR
VAR_OUTPUT
    Done : BOOL;
    Busy : BOOL;
    CommandBuffered : BOOL;
    Error : BOOL;
    ErrorID : UINT;
    LimitValues : ARRAY[0..1] OF REAL;
    J1_max : REAL;
    J2_max : REAL;
    J3_max : REAL;
    J4_max : REAL;
    J5_max : REAL;
    J6_max : REAL;
    J1_min : REAL;
    J2_min : REAL;
    J3_min : REAL;
    J4_min : REAL;
    J5_min : REAL;
    J6_min : REAL;
END_VAR
VAR_EXTERNAL
    PLC_CMDHeader : ARRAY[0..9] OF BYTE;
    EIP_OUT : ARRAY[0..255] OF BYTE;
    RobotCMDState : BYTE;
    Robot_CMDPayload : ARRAY[0..119] OF BYTE;
    Robot_CMDHeader : ARRAY[0..9] OF BYTE;
END_VAR
VAR
    _e1 : R_TRIG;
END_VAR
(* ladder, written here as Structured Text *)

(* Rung 0 *)
IF Execute THEN
    CMD := UINT#16#2011;
    CMDLength := 0;
END_IF;
(* Rung 1: #PLC to Robot# / CMD Header *)
IF Execute THEN
    ToAryByte(In := CMD, Order := _LOW_HIGH, AryOut := PLC_CMDHeader[0]);
    EIP_OUT[6] := PLC_CMDHeader[0];
    EIP_OUT[7] := PLC_CMDHeader[1];
    PLC_CMDHeader[2] := CMDLength;
    EIP_OUT[8] := PLC_CMDHeader[2];
END_IF;
(* Rung 2: #Robot to PLC# / CMD Header *)
_e1(CLK := Execute AND (RobotCMDState = BYTE#0));
Busy := _e1.Q;
Done := Execute AND (RobotCMDState = BYTE#0);
IF Execute THEN
    AryByteTo(In := Robot_CMDHeader[0], Size := UINT#2, Order := _LOW_HIGH, OutVal := CMD_Return);
    CMDLength_Return := Robot_CMDHeader[2];
END_IF;
(* Rung 3: #Robot to PLC# / CMD PayLoad *)
IF Execute THEN
    AryByteTo(In := Robot_CMDPayload[0], Size := UINT#4, Order := _LOW_HIGH, OutVal := J1_max);
    AryByteTo(In := Robot_CMDPayload[4], Size := UINT#4, Order := _LOW_HIGH, OutVal := J2_max);
    AryByteTo(In := Robot_CMDPayload[8], Size := UINT#4, Order := _LOW_HIGH, OutVal := J3_max);
    AryByteTo(In := Robot_CMDPayload[12], Size := UINT#4, Order := _LOW_HIGH, OutVal := J4_max);
    AryByteTo(In := Robot_CMDPayload[16], Size := UINT#4, Order := _LOW_HIGH, OutVal := J5_max);
    AryByteTo(In := Robot_CMDPayload[20], Size := UINT#4, Order := _LOW_HIGH, OutVal := J6_max);
    AryByteTo(In := Robot_CMDPayload[24], Size := UINT#4, Order := _LOW_HIGH, OutVal := J1_min);
    AryByteTo(In := Robot_CMDPayload[28], Size := UINT#4, Order := _LOW_HIGH, OutVal := J2_min);
    AryByteTo(In := Robot_CMDPayload[32], Size := UINT#4, Order := _LOW_HIGH, OutVal := J3_min);
    AryByteTo(In := Robot_CMDPayload[36], Size := UINT#4, Order := _LOW_HIGH, OutVal := J4_min);
    AryByteTo(In := Robot_CMDPayload[40], Size := UINT#4, Order := _LOW_HIGH, OutVal := J5_min);
    AryByteTo(In := Robot_CMDPayload[44], Size := UINT#4, Order := _LOW_HIGH, OutVal := J6_min);
END_IF;
END_FUNCTION_BLOCK

FUNCTION_BLOCK RC_GroupJog
VAR
    CMD : UINT;
    CMDLength : BYTE;
    CMD_Return : UINT;
    CMDLength_Return : BYTE;
END_VAR
VAR_INPUT
    Enable : BOOL;
    Vel : REAL;
    Acc : REAL;
    MaxDistance : REAL;
    MotionCMD : BYTE;
    JointNum : BYTE;
    Direction : BYTE;
    Control : BOOL;
    ToolNo : BYTE;
    FrameNo : BYTE;
    IncrementalTranslation : BOOL;
    IncrementalRotation : BOOL;
END_VAR
VAR_OUTPUT
    DistanceReached : BOOL;
    Busy : BOOL;
    CommandBuffered : BOOL;
    Enabled : BOOL;
    Active : BOOL;
    CommandAborted : BOOL;
    ParameterAccepted : BOOL;
    Error : BOOL;
    ErrorID : UINT;
END_VAR
VAR_EXTERNAL
    PLC_CMDHeader : ARRAY[0..9] OF BYTE;
    EIP_OUT : ARRAY[0..255] OF BYTE;
    RobotCMDState : BYTE;
    Robot_CMDPayload : ARRAY[0..119] OF BYTE;
    PLC_CMDPayload : ARRAY[0..238] OF BYTE;
    Robot_CMDHeader : ARRAY[0..9] OF BYTE;
END_VAR
VAR
    _e1 : R_TRIG;
    _e2 : F_TRIG;
    _e3 : R_TRIG;
    _e4 : F_TRIG;
    _e5 : R_TRIG;
    _e6 : R_TRIG;
    _e7 : F_TRIG;
    _e8 : R_TRIG;
END_VAR
(* ladder, written here as Structured Text *)

(* Rung 0 *)
Enabled := Enable;
(* Rung 1 *)
_e1(CLK := Enabled);
IF _e1.Q THEN
    CMD := UINT#16#3003;
    CMDLength := 15;
END_IF;
(* Rung 2 *)
_e2(CLK := Enabled);
IF _e2.Q THEN
    CMD := UINT#16#3004;
    CMDLength := 0;
END_IF;
(* Rung 3: #PLC to Robot# / CMD Header *)
_e3(CLK := Enabled);
_e4(CLK := Enabled);
IF _e3.Q OR _e4.Q THEN
    ToAryByte(In := CMD, Order := _LOW_HIGH, AryOut := PLC_CMDHeader[0]);
    EIP_OUT[6] := PLC_CMDHeader[0];
    EIP_OUT[7] := PLC_CMDHeader[1];
    PLC_CMDHeader[2] := CMDLength;
    EIP_OUT[8] := PLC_CMDHeader[2];
END_IF;
(* Rung 4: #PLC to Robot# / CMD PayLoad *)
_e5(CLK := Enabled);
IF _e5.Q THEN
    ToAryByte(In := Vel, Order := _LOW_HIGH, AryOut := PLC_CMDPayload[0]);
    AryMove(In := PLC_CMDPayload[0], AryOut := EIP_OUT[16], Size := UINT#4);
    ToAryByte(In := Acc, Order := _LOW_HIGH, AryOut := PLC_CMDPayload[4]);
    AryMove(In := PLC_CMDPayload[4], AryOut := EIP_OUT[20], Size := UINT#4);
    ToAryByte(In := MaxDistance, Order := _LOW_HIGH, AryOut := PLC_CMDPayload[8]);
    AryMove(In := PLC_CMDPayload[8], AryOut := EIP_OUT[24], Size := UINT#4);
    PLC_CMDPayload[12] := MotionCMD;
    EIP_OUT[28] := PLC_CMDPayload[12];
    PLC_CMDPayload[13] := JointNum;
    EIP_OUT[29] := PLC_CMDPayload[13];
    PLC_CMDPayload[14] := Direction;
    EIP_OUT[30] := PLC_CMDPayload[14];
END_IF;

(* Rung 5: #Robot to PLC# / CMD Header *)
_e6(CLK := Enabled);
_e7(CLK := Enabled);
_e8(CLK := (_e6.Q OR _e7.Q) AND (RobotCMDState = BYTE#0));
Busy := _e8.Q;
Active := (_e6.Q OR _e7.Q) AND (RobotCMDState = BYTE#0);
IF _e6.Q OR _e7.Q THEN
    AryByteTo(In := Robot_CMDHeader[0], Size := UINT#2, Order := _LOW_HIGH, OutVal := CMD_Return);
    CMDLength_Return := Robot_CMDHeader[2];
END_IF;
END_FUNCTION_BLOCK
